###############################################################
#  Generated by:      Cadence Innovus 21.35-s114_1
#  OS:                Linux x86_64(Host ID item0110.item.uni-bremen.de)
#  Generated on:      Fri Aug  9 22:37:40 2024
#  Design:            ibex_core
#  Command:           write_lef_abstract ./results/dummy_ni.lef -stripePin -noCutObs -PGPinLayers M3 -specifyTopLayer M3
###############################################################

VERSION 5.8 ;

BUSBITCHARS "[]" ;
DIVIDERCHAR "/" ;

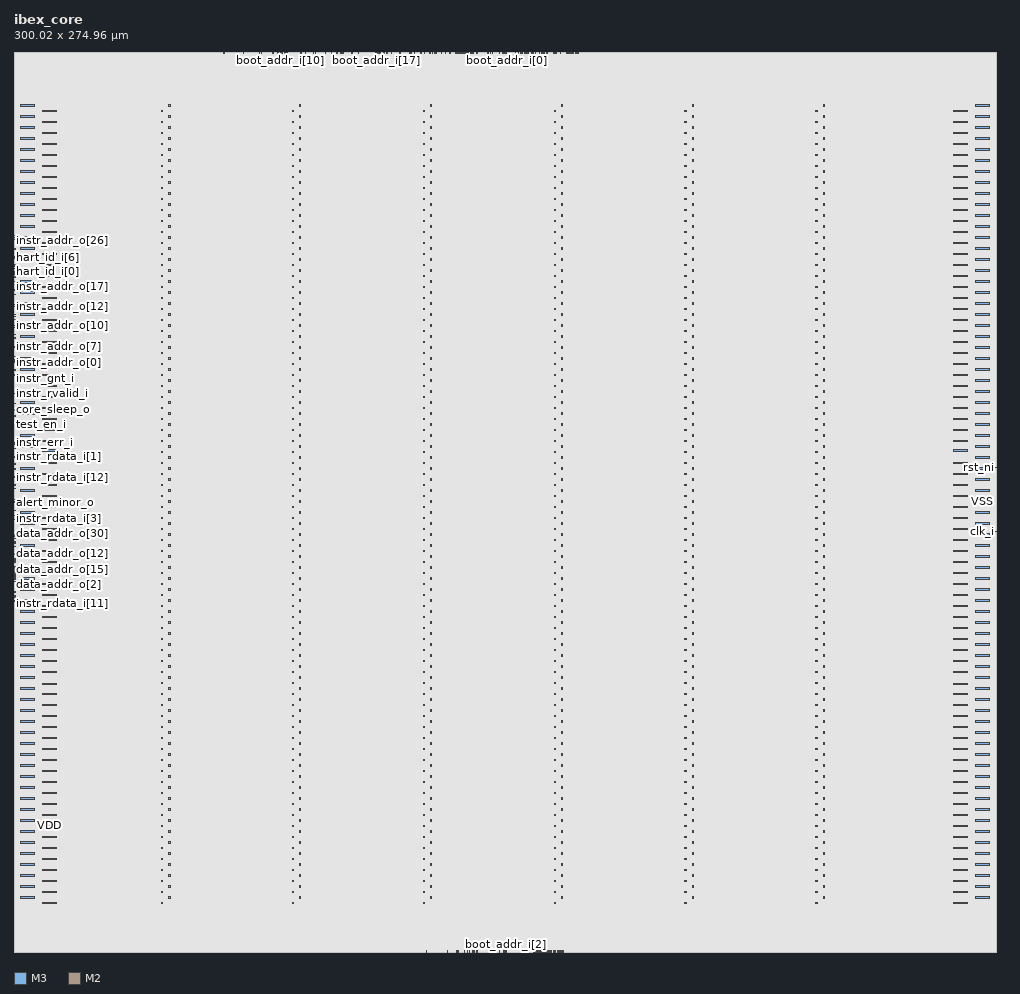
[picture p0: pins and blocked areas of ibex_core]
MACRO ibex_core
  CLASS BLOCK ;
  SIZE 300.020000 BY 274.960000 ;
  FOREIGN ibex_core 0.000000 0.000000 ;
  ORIGIN 0 0 ;
  SYMMETRY X Y R90 ;
  PIN clk_i
    DIRECTION INPUT ;
    USE SIGNAL ;
    PORT
      LAYER M3 ;
        RECT 299.630000 128.485000 300.020000 128.555000 ;
    END
  END clk_i
  PIN rst_ni
    DIRECTION INPUT ;
    USE SIGNAL ;
    PORT
      LAYER M3 ;
        RECT 299.630000 147.945000 300.020000 148.015000 ;
    END
  END rst_ni
  PIN test_en_i
    DIRECTION INPUT ;
    USE SIGNAL ;
    PORT
      LAYER M3 ;
        RECT 0.000000 163.485000 0.390000 163.555000 ;
    END
  END test_en_i
  PIN hart_id_i[31]
    DIRECTION INPUT ;
    USE SIGNAL ;
    PORT
      LAYER M2 ;
        RECT 99.855000 274.570000 99.925000 274.960000 ;
    END
  END hart_id_i[31]
  PIN hart_id_i[30]
    DIRECTION INPUT ;
    USE SIGNAL ;
    PORT
      LAYER M2 ;
        RECT 103.215000 274.570000 103.285000 274.960000 ;
    END
  END hart_id_i[30]
  PIN hart_id_i[29]
    DIRECTION INPUT ;
    USE SIGNAL ;
    PORT
      LAYER M2 ;
        RECT 127.715000 274.570000 127.785000 274.960000 ;
    END
  END hart_id_i[29]
  PIN hart_id_i[28]
    DIRECTION INPUT ;
    USE SIGNAL ;
    PORT
      LAYER M2 ;
        RECT 136.955000 274.570000 137.025000 274.960000 ;
    END
  END hart_id_i[28]
  PIN hart_id_i[27]
    DIRECTION INPUT ;
    USE SIGNAL ;
    PORT
      LAYER M2 ;
        RECT 137.795000 274.570000 137.865000 274.960000 ;
    END
  END hart_id_i[27]
  PIN hart_id_i[26]
    DIRECTION INPUT ;
    USE SIGNAL ;
    PORT
      LAYER M2 ;
        RECT 135.835000 274.570000 135.905000 274.960000 ;
    END
  END hart_id_i[26]
  PIN hart_id_i[25]
    DIRECTION INPUT ;
    USE SIGNAL ;
    PORT
      LAYER M2 ;
        RECT 137.515000 274.570000 137.585000 274.960000 ;
    END
  END hart_id_i[25]
  PIN hart_id_i[24]
    DIRECTION INPUT ;
    USE SIGNAL ;
    PORT
      LAYER M2 ;
        RECT 138.355000 274.570000 138.425000 274.960000 ;
    END
  END hart_id_i[24]
  PIN hart_id_i[23]
    DIRECTION INPUT ;
    USE SIGNAL ;
    PORT
      LAYER M2 ;
        RECT 139.335000 274.570000 139.405000 274.960000 ;
    END
  END hart_id_i[23]
  PIN hart_id_i[22]
    DIRECTION INPUT ;
    USE SIGNAL ;
    PORT
      LAYER M2 ;
        RECT 138.915000 274.570000 138.985000 274.960000 ;
    END
  END hart_id_i[22]
  PIN hart_id_i[21]
    DIRECTION INPUT ;
    USE SIGNAL ;
    PORT
      LAYER M2 ;
        RECT 110.355000 274.570000 110.425000 274.960000 ;
    END
  END hart_id_i[21]
  PIN hart_id_i[20]
    DIRECTION INPUT ;
    USE SIGNAL ;
    PORT
      LAYER M2 ;
        RECT 121.275000 274.570000 121.345000 274.960000 ;
    END
  END hart_id_i[20]
  PIN hart_id_i[19]
    DIRECTION INPUT ;
    USE SIGNAL ;
    PORT
      LAYER M2 ;
        RECT 113.715000 274.570000 113.785000 274.960000 ;
    END
  END hart_id_i[19]
  PIN hart_id_i[18]
    DIRECTION INPUT ;
    USE SIGNAL ;
    PORT
      LAYER M2 ;
        RECT 124.075000 274.570000 124.145000 274.960000 ;
    END
  END hart_id_i[18]
  PIN hart_id_i[17]
    DIRECTION INPUT ;
    USE SIGNAL ;
    PORT
      LAYER M2 ;
        RECT 111.055000 274.570000 111.125000 274.960000 ;
    END
  END hart_id_i[17]
  PIN hart_id_i[16]
    DIRECTION INPUT ;
    USE SIGNAL ;
    PORT
      LAYER M2 ;
        RECT 128.555000 274.570000 128.625000 274.960000 ;
    END
  END hart_id_i[16]
  PIN hart_id_i[15]
    DIRECTION INPUT ;
    USE SIGNAL ;
    PORT
      LAYER M2 ;
        RECT 100.695000 274.570000 100.765000 274.960000 ;
    END
  END hart_id_i[15]
  PIN hart_id_i[14]
    DIRECTION INPUT ;
    USE SIGNAL ;
    PORT
      LAYER M2 ;
        RECT 100.415000 274.570000 100.485000 274.960000 ;
    END
  END hart_id_i[14]
  PIN hart_id_i[13]
    DIRECTION INPUT ;
    USE SIGNAL ;
    PORT
      LAYER M2 ;
        RECT 91.455000 274.570000 91.525000 274.960000 ;
    END
  END hart_id_i[13]
  PIN hart_id_i[12]
    DIRECTION INPUT ;
    USE SIGNAL ;
    PORT
      LAYER M2 ;
        RECT 89.075000 274.570000 89.145000 274.960000 ;
    END
  END hart_id_i[12]
  PIN hart_id_i[11]
    DIRECTION INPUT ;
    USE SIGNAL ;
    PORT
      LAYER M2 ;
        RECT 80.815000 274.570000 80.885000 274.960000 ;
    END
  END hart_id_i[11]
  PIN hart_id_i[10]
    DIRECTION INPUT ;
    USE SIGNAL ;
    PORT
      LAYER M2 ;
        RECT 80.535000 274.570000 80.605000 274.960000 ;
    END
  END hart_id_i[10]
  PIN hart_id_i[9]
    DIRECTION INPUT ;
    USE SIGNAL ;
    PORT
      LAYER M2 ;
        RECT 83.335000 274.570000 83.405000 274.960000 ;
    END
  END hart_id_i[9]
  PIN hart_id_i[8]
    DIRECTION INPUT ;
    USE SIGNAL ;
    PORT
      LAYER M2 ;
        RECT 79.275000 274.570000 79.345000 274.960000 ;
    END
  END hart_id_i[8]
  PIN hart_id_i[7]
    DIRECTION INPUT ;
    USE SIGNAL ;
    PORT
      LAYER M3 ;
        RECT 0.000000 207.305000 0.390000 207.375000 ;
    END
  END hart_id_i[7]
  PIN hart_id_i[6]
    DIRECTION INPUT ;
    USE SIGNAL ;
    PORT
      LAYER M3 ;
        RECT 0.000000 212.205000 0.390000 212.275000 ;
    END
  END hart_id_i[6]
  PIN hart_id_i[5]
    DIRECTION INPUT ;
    USE SIGNAL ;
    PORT
      LAYER M2 ;
        RECT 64.155000 274.570000 64.225000 274.960000 ;
    END
  END hart_id_i[5]
  PIN hart_id_i[4]
    DIRECTION INPUT ;
    USE SIGNAL ;
    PORT
      LAYER M3 ;
        RECT 0.000000 207.585000 0.390000 207.655000 ;
    END
  END hart_id_i[4]
  PIN hart_id_i[3]
    DIRECTION INPUT ;
    USE SIGNAL ;
    PORT
      LAYER M2 ;
        RECT 75.495000 274.570000 75.565000 274.960000 ;
    END
  END hart_id_i[3]
  PIN hart_id_i[2]
    DIRECTION INPUT ;
    USE SIGNAL ;
    PORT
      LAYER M2 ;
        RECT 70.175000 274.570000 70.245000 274.960000 ;
    END
  END hart_id_i[2]
  PIN hart_id_i[1]
    DIRECTION INPUT ;
    USE SIGNAL ;
    PORT
      LAYER M3 ;
        RECT 0.000000 208.845000 0.390000 208.915000 ;
    END
  END hart_id_i[1]
  PIN hart_id_i[0]
    DIRECTION INPUT ;
    USE SIGNAL ;
    PORT
      LAYER M3 ;
        RECT 0.000000 207.865000 0.390000 207.935000 ;
    END
  END hart_id_i[0]
  PIN boot_addr_i[31]
    DIRECTION INPUT ;
    USE SIGNAL ;
    PORT
      LAYER M2 ;
        RECT 95.235000 274.570000 95.305000 274.960000 ;
    END
  END boot_addr_i[31]
  PIN boot_addr_i[30]
    DIRECTION INPUT ;
    USE SIGNAL ;
    PORT
      LAYER M2 ;
        RECT 105.315000 274.570000 105.385000 274.960000 ;
    END
  END boot_addr_i[30]
  PIN boot_addr_i[29]
    DIRECTION INPUT ;
    USE SIGNAL ;
    PORT
      LAYER M2 ;
        RECT 113.015000 274.570000 113.085000 274.960000 ;
    END
  END boot_addr_i[29]
  PIN boot_addr_i[28]
    DIRECTION INPUT ;
    USE SIGNAL ;
    PORT
      LAYER M2 ;
        RECT 128.975000 274.570000 129.045000 274.960000 ;
    END
  END boot_addr_i[28]
  PIN boot_addr_i[27]
    DIRECTION INPUT ;
    USE SIGNAL ;
    PORT
      LAYER M2 ;
        RECT 133.175000 274.570000 133.245000 274.960000 ;
    END
  END boot_addr_i[27]
  PIN boot_addr_i[26]
    DIRECTION INPUT ;
    USE SIGNAL ;
    PORT
      LAYER M2 ;
        RECT 135.135000 274.570000 135.205000 274.960000 ;
    END
  END boot_addr_i[26]
  PIN boot_addr_i[25]
    DIRECTION INPUT ;
    USE SIGNAL ;
    PORT
      LAYER M2 ;
        RECT 134.855000 274.570000 134.925000 274.960000 ;
    END
  END boot_addr_i[25]
  PIN boot_addr_i[24]
    DIRECTION INPUT ;
    USE SIGNAL ;
    PORT
      LAYER M2 ;
        RECT 136.395000 274.570000 136.465000 274.960000 ;
    END
  END boot_addr_i[24]
  PIN boot_addr_i[23]
    DIRECTION INPUT ;
    USE SIGNAL ;
    PORT
      LAYER M2 ;
        RECT 136.675000 274.570000 136.745000 274.960000 ;
    END
  END boot_addr_i[23]
  PIN boot_addr_i[22]
    DIRECTION INPUT ;
    USE SIGNAL ;
    PORT
      LAYER M2 ;
        RECT 131.775000 274.570000 131.845000 274.960000 ;
    END
  END boot_addr_i[22]
  PIN boot_addr_i[21]
    DIRECTION INPUT ;
    USE SIGNAL ;
    PORT
      LAYER M2 ;
        RECT 112.035000 274.570000 112.105000 274.960000 ;
    END
  END boot_addr_i[21]
  PIN boot_addr_i[20]
    DIRECTION INPUT ;
    USE SIGNAL ;
    PORT
      LAYER M2 ;
        RECT 115.395000 274.570000 115.465000 274.960000 ;
    END
  END boot_addr_i[20]
  PIN boot_addr_i[19]
    DIRECTION INPUT ;
    USE SIGNAL ;
    PORT
      LAYER M2 ;
        RECT 122.255000 274.570000 122.325000 274.960000 ;
    END
  END boot_addr_i[19]
  PIN boot_addr_i[18]
    DIRECTION INPUT ;
    USE SIGNAL ;
    PORT
      LAYER M2 ;
        RECT 125.475000 274.570000 125.545000 274.960000 ;
    END
  END boot_addr_i[18]
  PIN boot_addr_i[17]
    DIRECTION INPUT ;
    USE SIGNAL ;
    PORT
      LAYER M2 ;
        RECT 110.775000 274.570000 110.845000 274.960000 ;
    END
  END boot_addr_i[17]
  PIN boot_addr_i[16]
    DIRECTION INPUT ;
    USE SIGNAL ;
    PORT
      LAYER M2 ;
        RECT 127.295000 274.570000 127.365000 274.960000 ;
    END
  END boot_addr_i[16]
  PIN boot_addr_i[15]
    DIRECTION INPUT ;
    USE SIGNAL ;
    PORT
      LAYER M2 ;
        RECT 98.595000 274.570000 98.665000 274.960000 ;
    END
  END boot_addr_i[15]
  PIN boot_addr_i[14]
    DIRECTION INPUT ;
    USE SIGNAL ;
    PORT
      LAYER M2 ;
        RECT 96.915000 274.570000 96.985000 274.960000 ;
    END
  END boot_addr_i[14]
  PIN boot_addr_i[13]
    DIRECTION INPUT ;
    USE SIGNAL ;
    PORT
      LAYER M2 ;
        RECT 92.015000 274.570000 92.085000 274.960000 ;
    END
  END boot_addr_i[13]
  PIN boot_addr_i[12]
    DIRECTION INPUT ;
    USE SIGNAL ;
    PORT
      LAYER M2 ;
        RECT 87.675000 274.570000 87.745000 274.960000 ;
    END
  END boot_addr_i[12]
  PIN boot_addr_i[11]
    DIRECTION INPUT ;
    USE SIGNAL ;
    PORT
      LAYER M2 ;
        RECT 82.775000 274.570000 82.845000 274.960000 ;
    END
  END boot_addr_i[11]
  PIN boot_addr_i[10]
    DIRECTION INPUT ;
    USE SIGNAL ;
    PORT
      LAYER M2 ;
        RECT 81.515000 274.570000 81.585000 274.960000 ;
    END
  END boot_addr_i[10]
  PIN boot_addr_i[9]
    DIRECTION INPUT ;
    USE SIGNAL ;
    PORT
      LAYER M2 ;
        RECT 83.615000 274.570000 83.685000 274.960000 ;
    END
  END boot_addr_i[9]
  PIN boot_addr_i[8]
    DIRECTION INPUT ;
    USE SIGNAL ;
    PORT
      LAYER M2 ;
        RECT 82.075000 274.570000 82.145000 274.960000 ;
    END
  END boot_addr_i[8]
  PIN boot_addr_i[7]
    DIRECTION INPUT ;
    USE SIGNAL ;
    PORT
      LAYER M2 ;
        RECT 149.975000 274.570000 150.045000 274.960000 ;
    END
  END boot_addr_i[7]
  PIN boot_addr_i[6]
    DIRECTION INPUT ;
    USE SIGNAL ;
    PORT
      LAYER M2 ;
        RECT 149.975000 0.000000 150.045000 0.390000 ;
    END
  END boot_addr_i[6]
  PIN boot_addr_i[5]
    DIRECTION INPUT ;
    USE SIGNAL ;
    PORT
      LAYER M2 ;
        RECT 149.695000 274.570000 149.765000 274.960000 ;
    END
  END boot_addr_i[5]
  PIN boot_addr_i[4]
    DIRECTION INPUT ;
    USE SIGNAL ;
    PORT
      LAYER M2 ;
        RECT 150.255000 274.570000 150.325000 274.960000 ;
    END
  END boot_addr_i[4]
  PIN boot_addr_i[3]
    DIRECTION INPUT ;
    USE SIGNAL ;
    PORT
      LAYER M2 ;
        RECT 149.695000 0.000000 149.765000 0.390000 ;
    END
  END boot_addr_i[3]
  PIN boot_addr_i[2]
    DIRECTION INPUT ;
    USE SIGNAL ;
    PORT
      LAYER M2 ;
        RECT 150.255000 0.000000 150.325000 0.390000 ;
    END
  END boot_addr_i[2]
  PIN boot_addr_i[1]
    DIRECTION INPUT ;
    USE SIGNAL ;
    PORT
      LAYER M2 ;
        RECT 149.415000 274.570000 149.485000 274.960000 ;
    END
  END boot_addr_i[1]
  PIN boot_addr_i[0]
    DIRECTION INPUT ;
    USE SIGNAL ;
    PORT
      LAYER M2 ;
        RECT 150.535000 274.570000 150.605000 274.960000 ;
    END
  END boot_addr_i[0]
  PIN instr_req_o
    DIRECTION OUTPUT ;
    USE SIGNAL ;
    PORT
      LAYER M3 ;
        RECT 0.000000 176.225000 0.390000 176.295000 ;
    END
  END instr_req_o
  PIN instr_gnt_i
    DIRECTION INPUT ;
    USE SIGNAL ;
    PORT
      LAYER M3 ;
        RECT 0.000000 177.625000 0.390000 177.695000 ;
    END
  END instr_gnt_i
  PIN instr_rvalid_i
    DIRECTION INPUT ;
    USE SIGNAL ;
    PORT
      LAYER M3 ;
        RECT 0.000000 170.485000 0.390000 170.555000 ;
    END
  END instr_rvalid_i
  PIN instr_addr_o[31]
    DIRECTION OUTPUT ;
    USE SIGNAL ;
    PORT
      LAYER M3 ;
        RECT 0.000000 214.725000 0.390000 214.795000 ;
    END
  END instr_addr_o[31]
  PIN instr_addr_o[30]
    DIRECTION OUTPUT ;
    USE SIGNAL ;
    PORT
      LAYER M3 ;
        RECT 0.000000 218.365000 0.390000 218.435000 ;
    END
  END instr_addr_o[30]
  PIN instr_addr_o[29]
    DIRECTION OUTPUT ;
    USE SIGNAL ;
    PORT
      LAYER M3 ;
        RECT 0.000000 218.785000 0.390000 218.855000 ;
    END
  END instr_addr_o[29]
  PIN instr_addr_o[28]
    DIRECTION OUTPUT ;
    USE SIGNAL ;
    PORT
      LAYER M3 ;
        RECT 0.000000 217.525000 0.390000 217.595000 ;
    END
  END instr_addr_o[28]
  PIN instr_addr_o[27]
    DIRECTION OUTPUT ;
    USE SIGNAL ;
    PORT
      LAYER M3 ;
        RECT 0.000000 211.925000 0.390000 211.995000 ;
    END
  END instr_addr_o[27]
  PIN instr_addr_o[26]
    DIRECTION OUTPUT ;
    USE SIGNAL ;
    PORT
      LAYER M3 ;
        RECT 0.000000 215.005000 0.390000 215.075000 ;
    END
  END instr_addr_o[26]
  PIN instr_addr_o[25]
    DIRECTION OUTPUT ;
    USE SIGNAL ;
    PORT
      LAYER M3 ;
        RECT 0.000000 209.545000 0.390000 209.615000 ;
    END
  END instr_addr_o[25]
  PIN instr_addr_o[24]
    DIRECTION OUTPUT ;
    USE SIGNAL ;
    PORT
      LAYER M3 ;
        RECT 0.000000 212.485000 0.390000 212.555000 ;
    END
  END instr_addr_o[24]
  PIN instr_addr_o[23]
    DIRECTION OUTPUT ;
    USE SIGNAL ;
    PORT
      LAYER M3 ;
        RECT 0.000000 207.025000 0.390000 207.095000 ;
    END
  END instr_addr_o[23]
  PIN instr_addr_o[22]
    DIRECTION OUTPUT ;
    USE SIGNAL ;
    PORT
      LAYER M3 ;
        RECT 0.000000 209.825000 0.390000 209.895000 ;
    END
  END instr_addr_o[22]
  PIN instr_addr_o[21]
    DIRECTION OUTPUT ;
    USE SIGNAL ;
    PORT
      LAYER M3 ;
        RECT 0.000000 206.185000 0.390000 206.255000 ;
    END
  END instr_addr_o[21]
  PIN instr_addr_o[20]
    DIRECTION OUTPUT ;
    USE SIGNAL ;
    PORT
      LAYER M3 ;
        RECT 0.000000 204.925000 0.390000 204.995000 ;
    END
  END instr_addr_o[20]
  PIN instr_addr_o[19]
    DIRECTION OUTPUT ;
    USE SIGNAL ;
    PORT
      LAYER M3 ;
        RECT 0.000000 201.985000 0.390000 202.055000 ;
    END
  END instr_addr_o[19]
  PIN instr_addr_o[18]
    DIRECTION OUTPUT ;
    USE SIGNAL ;
    PORT
      LAYER M3 ;
        RECT 0.000000 202.265000 0.390000 202.335000 ;
    END
  END instr_addr_o[18]
  PIN instr_addr_o[17]
    DIRECTION OUTPUT ;
    USE SIGNAL ;
    PORT
      LAYER M3 ;
        RECT 0.000000 200.725000 0.390000 200.795000 ;
    END
  END instr_addr_o[17]
  PIN instr_addr_o[16]
    DIRECTION OUTPUT ;
    USE SIGNAL ;
    PORT
      LAYER M3 ;
        RECT 0.000000 197.785000 0.390000 197.855000 ;
    END
  END instr_addr_o[16]
  PIN instr_addr_o[15]
    DIRECTION OUTPUT ;
    USE SIGNAL ;
    PORT
      LAYER M3 ;
        RECT 0.000000 197.085000 0.390000 197.155000 ;
    END
  END instr_addr_o[15]
  PIN instr_addr_o[14]
    DIRECTION OUTPUT ;
    USE SIGNAL ;
    PORT
      LAYER M3 ;
        RECT 0.000000 194.005000 0.390000 194.075000 ;
    END
  END instr_addr_o[14]
  PIN instr_addr_o[13]
    DIRECTION OUTPUT ;
    USE SIGNAL ;
    PORT
      LAYER M3 ;
        RECT 0.000000 193.165000 0.390000 193.235000 ;
    END
  END instr_addr_o[13]
  PIN instr_addr_o[12]
    DIRECTION OUTPUT ;
    USE SIGNAL ;
    PORT
      LAYER M3 ;
        RECT 0.000000 194.845000 0.390000 194.915000 ;
    END
  END instr_addr_o[12]
  PIN instr_addr_o[11]
    DIRECTION OUTPUT ;
    USE SIGNAL ;
    PORT
      LAYER M3 ;
        RECT 0.000000 188.545000 0.390000 188.615000 ;
    END
  END instr_addr_o[11]
  PIN instr_addr_o[10]
    DIRECTION OUTPUT ;
    USE SIGNAL ;
    PORT
      LAYER M3 ;
        RECT 0.000000 191.485000 0.390000 191.555000 ;
    END
  END instr_addr_o[10]
  PIN instr_addr_o[9]
    DIRECTION OUTPUT ;
    USE SIGNAL ;
    PORT
      LAYER M3 ;
        RECT 0.000000 187.705000 0.390000 187.775000 ;
    END
  END instr_addr_o[9]
  PIN instr_addr_o[8]
    DIRECTION OUTPUT ;
    USE SIGNAL ;
    PORT
      LAYER M3 ;
        RECT 0.000000 190.645000 0.390000 190.715000 ;
    END
  END instr_addr_o[8]
  PIN instr_addr_o[7]
    DIRECTION OUTPUT ;
    USE SIGNAL ;
    PORT
      LAYER M3 ;
        RECT 0.000000 187.285000 0.390000 187.355000 ;
    END
  END instr_addr_o[7]
  PIN instr_addr_o[6]
    DIRECTION OUTPUT ;
    USE SIGNAL ;
    PORT
      LAYER M3 ;
        RECT 0.000000 184.765000 0.390000 184.835000 ;
    END
  END instr_addr_o[6]
  PIN instr_addr_o[5]
    DIRECTION OUTPUT ;
    USE SIGNAL ;
    PORT
      LAYER M3 ;
        RECT 0.000000 181.825000 0.390000 181.895000 ;
    END
  END instr_addr_o[5]
  PIN instr_addr_o[4]
    DIRECTION OUTPUT ;
    USE SIGNAL ;
    PORT
      LAYER M3 ;
        RECT 0.000000 185.045000 0.390000 185.115000 ;
    END
  END instr_addr_o[4]
  PIN instr_addr_o[3]
    DIRECTION OUTPUT ;
    USE SIGNAL ;
    PORT
      LAYER M3 ;
        RECT 0.000000 180.985000 0.390000 181.055000 ;
    END
  END instr_addr_o[3]
  PIN instr_addr_o[2]
    DIRECTION OUTPUT ;
    USE SIGNAL ;
    PORT
      LAYER M3 ;
        RECT 0.000000 180.565000 0.390000 180.635000 ;
    END
  END instr_addr_o[2]
  PIN instr_addr_o[1]
    DIRECTION OUTPUT ;
    USE SIGNAL ;
    PORT
      LAYER M3 ;
        RECT 0.000000 180.285000 0.390000 180.355000 ;
    END
  END instr_addr_o[1]
  PIN instr_addr_o[0]
    DIRECTION OUTPUT ;
    USE SIGNAL ;
    PORT
      LAYER M3 ;
        RECT 0.000000 180.005000 0.390000 180.075000 ;
    END
  END instr_addr_o[0]
  PIN instr_rdata_i[31]
    DIRECTION INPUT ;
    USE SIGNAL ;
    PORT
      LAYER M3 ;
        RECT 0.000000 124.985000 0.390000 125.055000 ;
    END
  END instr_rdata_i[31]
  PIN instr_rdata_i[30]
    DIRECTION INPUT ;
    USE SIGNAL ;
    PORT
      LAYER M3 ;
        RECT 0.000000 126.385000 0.390000 126.455000 ;
    END
  END instr_rdata_i[30]
  PIN instr_rdata_i[29]
    DIRECTION INPUT ;
    USE SIGNAL ;
    PORT
      LAYER M3 ;
        RECT 0.000000 119.385000 0.390000 119.455000 ;
    END
  END instr_rdata_i[29]
  PIN instr_rdata_i[28]
    DIRECTION INPUT ;
    USE SIGNAL ;
    PORT
      LAYER M3 ;
        RECT 0.000000 149.065000 0.390000 149.135000 ;
    END
  END instr_rdata_i[28]
  PIN instr_rdata_i[27]
    DIRECTION INPUT ;
    USE SIGNAL ;
    PORT
      LAYER M3 ;
        RECT 0.000000 110.145000 0.390000 110.215000 ;
    END
  END instr_rdata_i[27]
  PIN instr_rdata_i[26]
    DIRECTION INPUT ;
    USE SIGNAL ;
    PORT
      LAYER M3 ;
        RECT 0.000000 127.365000 0.390000 127.435000 ;
    END
  END instr_rdata_i[26]
  PIN instr_rdata_i[25]
    DIRECTION INPUT ;
    USE SIGNAL ;
    PORT
      LAYER M3 ;
        RECT 0.000000 133.385000 0.390000 133.455000 ;
    END
  END instr_rdata_i[25]
  PIN instr_rdata_i[24]
    DIRECTION INPUT ;
    USE SIGNAL ;
    PORT
      LAYER M3 ;
        RECT 0.000000 147.525000 0.390000 147.595000 ;
    END
  END instr_rdata_i[24]
  PIN instr_rdata_i[23]
    DIRECTION INPUT ;
    USE SIGNAL ;
    PORT
      LAYER M3 ;
        RECT 0.000000 142.765000 0.390000 142.835000 ;
    END
  END instr_rdata_i[23]
  PIN instr_rdata_i[22]
    DIRECTION INPUT ;
    USE SIGNAL ;
    PORT
      LAYER M3 ;
        RECT 0.000000 115.745000 0.390000 115.815000 ;
    END
  END instr_rdata_i[22]
  PIN instr_rdata_i[21]
    DIRECTION INPUT ;
    USE SIGNAL ;
    PORT
      LAYER M3 ;
        RECT 0.000000 108.605000 0.390000 108.675000 ;
    END
  END instr_rdata_i[21]
  PIN instr_rdata_i[20]
    DIRECTION INPUT ;
    USE SIGNAL ;
    PORT
      LAYER M3 ;
        RECT 0.000000 145.145000 0.390000 145.215000 ;
    END
  END instr_rdata_i[20]
  PIN instr_rdata_i[19]
    DIRECTION INPUT ;
    USE SIGNAL ;
    PORT
      LAYER M3 ;
        RECT 0.000000 138.145000 0.390000 138.215000 ;
    END
  END instr_rdata_i[19]
  PIN instr_rdata_i[18]
    DIRECTION INPUT ;
    USE SIGNAL ;
    PORT
      LAYER M3 ;
        RECT 0.000000 131.985000 0.390000 132.055000 ;
    END
  END instr_rdata_i[18]
  PIN instr_rdata_i[17]
    DIRECTION INPUT ;
    USE SIGNAL ;
    PORT
      LAYER M3 ;
        RECT 0.000000 153.685000 0.390000 153.755000 ;
    END
  END instr_rdata_i[17]
  PIN instr_rdata_i[16]
    DIRECTION INPUT ;
    USE SIGNAL ;
    PORT
      LAYER M3 ;
        RECT 0.000000 155.085000 0.390000 155.155000 ;
    END
  END instr_rdata_i[16]
  PIN instr_rdata_i[15]
    DIRECTION INPUT ;
    USE SIGNAL ;
    PORT
      LAYER M3 ;
        RECT 0.000000 119.665000 0.390000 119.735000 ;
    END
  END instr_rdata_i[15]
  PIN instr_rdata_i[14]
    DIRECTION INPUT ;
    USE SIGNAL ;
    PORT
      LAYER M3 ;
        RECT 0.000000 109.865000 0.390000 109.935000 ;
    END
  END instr_rdata_i[14]
  PIN instr_rdata_i[13]
    DIRECTION INPUT ;
    USE SIGNAL ;
    PORT
      LAYER M3 ;
        RECT 0.000000 108.325000 0.390000 108.395000 ;
    END
  END instr_rdata_i[13]
  PIN instr_rdata_i[12]
    DIRECTION INPUT ;
    USE SIGNAL ;
    PORT
      LAYER M3 ;
        RECT 0.000000 144.865000 0.390000 144.935000 ;
    END
  END instr_rdata_i[12]
  PIN instr_rdata_i[11]
    DIRECTION INPUT ;
    USE SIGNAL ;
    PORT
      LAYER M3 ;
        RECT 0.000000 108.885000 0.390000 108.955000 ;
    END
  END instr_rdata_i[11]
  PIN instr_rdata_i[10]
    DIRECTION INPUT ;
    USE SIGNAL ;
    PORT
      LAYER M3 ;
        RECT 0.000000 117.705000 0.390000 117.775000 ;
    END
  END instr_rdata_i[10]
  PIN instr_rdata_i[9]
    DIRECTION INPUT ;
    USE SIGNAL ;
    PORT
      LAYER M3 ;
        RECT 0.000000 124.705000 0.390000 124.775000 ;
    END
  END instr_rdata_i[9]
  PIN instr_rdata_i[8]
    DIRECTION INPUT ;
    USE SIGNAL ;
    PORT
      LAYER M3 ;
        RECT 0.000000 141.645000 0.390000 141.715000 ;
    END
  END instr_rdata_i[8]
  PIN instr_rdata_i[7]
    DIRECTION INPUT ;
    USE SIGNAL ;
    PORT
      LAYER M3 ;
        RECT 0.000000 137.585000 0.390000 137.655000 ;
    END
  END instr_rdata_i[7]
  PIN instr_rdata_i[6]
    DIRECTION INPUT ;
    USE SIGNAL ;
    PORT
      LAYER M3 ;
        RECT 0.000000 113.225000 0.390000 113.295000 ;
    END
  END instr_rdata_i[6]
  PIN instr_rdata_i[5]
    DIRECTION INPUT ;
    USE SIGNAL ;
    PORT
      LAYER M3 ;
        RECT 0.000000 107.205000 0.390000 107.275000 ;
    END
  END instr_rdata_i[5]
  PIN instr_rdata_i[4]
    DIRECTION INPUT ;
    USE SIGNAL ;
    PORT
      LAYER M3 ;
        RECT 0.000000 142.485000 0.390000 142.555000 ;
    END
  END instr_rdata_i[4]
  PIN instr_rdata_i[3]
    DIRECTION INPUT ;
    USE SIGNAL ;
    PORT
      LAYER M3 ;
        RECT 0.000000 134.925000 0.390000 134.995000 ;
    END
  END instr_rdata_i[3]
  PIN instr_rdata_i[2]
    DIRECTION INPUT ;
    USE SIGNAL ;
    PORT
      LAYER M3 ;
        RECT 0.000000 127.085000 0.390000 127.155000 ;
    END
  END instr_rdata_i[2]
  PIN instr_rdata_i[1]
    DIRECTION INPUT ;
    USE SIGNAL ;
    PORT
      LAYER M3 ;
        RECT 0.000000 148.785000 0.390000 148.855000 ;
    END
  END instr_rdata_i[1]
  PIN instr_rdata_i[0]
    DIRECTION INPUT ;
    USE SIGNAL ;
    PORT
      LAYER M3 ;
        RECT 0.000000 151.165000 0.390000 151.235000 ;
    END
  END instr_rdata_i[0]
  PIN instr_err_i
    DIRECTION INPUT ;
    USE SIGNAL ;
    PORT
      LAYER M3 ;
        RECT 0.000000 155.505000 0.390000 155.575000 ;
    END
  END instr_err_i
  PIN data_req_o
    DIRECTION OUTPUT ;
    USE SIGNAL ;
    PORT
      LAYER M2 ;
        RECT 145.495000 274.570000 145.565000 274.960000 ;
    END
  END data_req_o
  PIN data_gnt_i
    DIRECTION INPUT ;
    USE SIGNAL ;
    PORT
      LAYER M2 ;
        RECT 148.295000 274.570000 148.365000 274.960000 ;
    END
  END data_gnt_i
  PIN data_rvalid_i
    DIRECTION INPUT ;
    USE SIGNAL ;
    PORT
      LAYER M2 ;
        RECT 144.795000 274.570000 144.865000 274.960000 ;
    END
  END data_rvalid_i
  PIN data_we_o
    DIRECTION OUTPUT ;
    USE SIGNAL ;
    PORT
      LAYER M2 ;
        RECT 113.995000 274.570000 114.065000 274.960000 ;
    END
  END data_we_o
  PIN data_be_o[3]
    DIRECTION OUTPUT ;
    USE SIGNAL ;
    PORT
      LAYER M2 ;
        RECT 156.275000 274.570000 156.345000 274.960000 ;
    END
  END data_be_o[3]
  PIN data_be_o[2]
    DIRECTION OUTPUT ;
    USE SIGNAL ;
    PORT
      LAYER M2 ;
        RECT 160.475000 274.570000 160.545000 274.960000 ;
    END
  END data_be_o[2]
  PIN data_be_o[1]
    DIRECTION OUTPUT ;
    USE SIGNAL ;
    PORT
      LAYER M2 ;
        RECT 159.215000 274.570000 159.285000 274.960000 ;
    END
  END data_be_o[1]
  PIN data_be_o[0]
    DIRECTION OUTPUT ;
    USE SIGNAL ;
    PORT
      LAYER M2 ;
        RECT 161.175000 274.570000 161.245000 274.960000 ;
    END
  END data_be_o[0]
  PIN data_addr_o[31]
    DIRECTION OUTPUT ;
    USE SIGNAL ;
    PORT
      LAYER M3 ;
        RECT 0.000000 123.865000 0.390000 123.935000 ;
    END
  END data_addr_o[31]
  PIN data_addr_o[30]
    DIRECTION OUTPUT ;
    USE SIGNAL ;
    PORT
      LAYER M3 ;
        RECT 0.000000 125.405000 0.390000 125.475000 ;
    END
  END data_addr_o[30]
  PIN data_addr_o[29]
    DIRECTION OUTPUT ;
    USE SIGNAL ;
    PORT
      LAYER M2 ;
        RECT 126.035000 0.000000 126.105000 0.390000 ;
    END
  END data_addr_o[29]
  PIN data_addr_o[28]
    DIRECTION OUTPUT ;
    USE SIGNAL ;
    PORT
      LAYER M2 ;
        RECT 132.475000 0.000000 132.545000 0.390000 ;
    END
  END data_addr_o[28]
  PIN data_addr_o[27]
    DIRECTION OUTPUT ;
    USE SIGNAL ;
    PORT
      LAYER M2 ;
        RECT 135.835000 0.000000 135.905000 0.390000 ;
    END
  END data_addr_o[27]
  PIN data_addr_o[26]
    DIRECTION OUTPUT ;
    USE SIGNAL ;
    PORT
      LAYER M2 ;
        RECT 139.055000 0.000000 139.125000 0.390000 ;
    END
  END data_addr_o[26]
  PIN data_addr_o[25]
    DIRECTION OUTPUT ;
    USE SIGNAL ;
    PORT
      LAYER M2 ;
        RECT 141.435000 0.000000 141.505000 0.390000 ;
    END
  END data_addr_o[25]
  PIN data_addr_o[24]
    DIRECTION OUTPUT ;
    USE SIGNAL ;
    PORT
      LAYER M2 ;
        RECT 145.635000 0.000000 145.705000 0.390000 ;
    END
  END data_addr_o[24]
  PIN data_addr_o[23]
    DIRECTION OUTPUT ;
    USE SIGNAL ;
    PORT
      LAYER M2 ;
        RECT 145.915000 0.000000 145.985000 0.390000 ;
    END
  END data_addr_o[23]
  PIN data_addr_o[22]
    DIRECTION OUTPUT ;
    USE SIGNAL ;
    PORT
      LAYER M2 ;
        RECT 148.295000 0.000000 148.365000 0.390000 ;
    END
  END data_addr_o[22]
  PIN data_addr_o[21]
    DIRECTION OUTPUT ;
    USE SIGNAL ;
    PORT
      LAYER M2 ;
        RECT 140.455000 0.000000 140.525000 0.390000 ;
    END
  END data_addr_o[21]
  PIN data_addr_o[20]
    DIRECTION OUTPUT ;
    USE SIGNAL ;
    PORT
      LAYER M2 ;
        RECT 140.735000 0.000000 140.805000 0.390000 ;
    END
  END data_addr_o[20]
  PIN data_addr_o[19]
    DIRECTION OUTPUT ;
    USE SIGNAL ;
    PORT
      LAYER M2 ;
        RECT 140.175000 0.000000 140.245000 0.390000 ;
    END
  END data_addr_o[19]
  PIN data_addr_o[18]
    DIRECTION OUTPUT ;
    USE SIGNAL ;
    PORT
      LAYER M2 ;
        RECT 138.495000 0.000000 138.565000 0.390000 ;
    END
  END data_addr_o[18]
  PIN data_addr_o[17]
    DIRECTION OUTPUT ;
    USE SIGNAL ;
    PORT
      LAYER M2 ;
        RECT 137.655000 0.000000 137.725000 0.390000 ;
    END
  END data_addr_o[17]
  PIN data_addr_o[16]
    DIRECTION OUTPUT ;
    USE SIGNAL ;
    PORT
      LAYER M2 ;
        RECT 135.275000 0.000000 135.345000 0.390000 ;
    END
  END data_addr_o[16]
  PIN data_addr_o[15]
    DIRECTION OUTPUT ;
    USE SIGNAL ;
    PORT
      LAYER M3 ;
        RECT 0.000000 119.105000 0.390000 119.175000 ;
    END
  END data_addr_o[15]
  PIN data_addr_o[14]
    DIRECTION OUTPUT ;
    USE SIGNAL ;
    PORT
      LAYER M3 ;
        RECT 0.000000 120.225000 0.390000 120.295000 ;
    END
  END data_addr_o[14]
  PIN data_addr_o[13]
    DIRECTION OUTPUT ;
    USE SIGNAL ;
    PORT
      LAYER M3 ;
        RECT 0.000000 121.485000 0.390000 121.555000 ;
    END
  END data_addr_o[13]
  PIN data_addr_o[12]
    DIRECTION OUTPUT ;
    USE SIGNAL ;
    PORT
      LAYER M3 ;
        RECT 0.000000 121.765000 0.390000 121.835000 ;
    END
  END data_addr_o[12]
  PIN data_addr_o[11]
    DIRECTION OUTPUT ;
    USE SIGNAL ;
    PORT
      LAYER M3 ;
        RECT 0.000000 116.445000 0.390000 116.515000 ;
    END
  END data_addr_o[11]
  PIN data_addr_o[10]
    DIRECTION OUTPUT ;
    USE SIGNAL ;
    PORT
      LAYER M3 ;
        RECT 0.000000 117.145000 0.390000 117.215000 ;
    END
  END data_addr_o[10]
  PIN data_addr_o[9]
    DIRECTION OUTPUT ;
    USE SIGNAL ;
    PORT
      LAYER M3 ;
        RECT 0.000000 117.425000 0.390000 117.495000 ;
    END
  END data_addr_o[9]
  PIN data_addr_o[8]
    DIRECTION OUTPUT ;
    USE SIGNAL ;
    PORT
      LAYER M3 ;
        RECT 0.000000 119.945000 0.390000 120.015000 ;
    END
  END data_addr_o[8]
  PIN data_addr_o[7]
    DIRECTION OUTPUT ;
    USE SIGNAL ;
    PORT
      LAYER M3 ;
        RECT 0.000000 116.025000 0.390000 116.095000 ;
    END
  END data_addr_o[7]
  PIN data_addr_o[6]
    DIRECTION OUTPUT ;
    USE SIGNAL ;
    PORT
      LAYER M3 ;
        RECT 0.000000 114.345000 0.390000 114.415000 ;
    END
  END data_addr_o[6]
  PIN data_addr_o[5]
    DIRECTION OUTPUT ;
    USE SIGNAL ;
    PORT
      LAYER M3 ;
        RECT 0.000000 116.725000 0.390000 116.795000 ;
    END
  END data_addr_o[5]
  PIN data_addr_o[4]
    DIRECTION OUTPUT ;
    USE SIGNAL ;
    PORT
      LAYER M3 ;
        RECT 0.000000 115.465000 0.390000 115.535000 ;
    END
  END data_addr_o[4]
  PIN data_addr_o[3]
    DIRECTION OUTPUT ;
    USE SIGNAL ;
    PORT
      LAYER M3 ;
        RECT 0.000000 115.045000 0.390000 115.115000 ;
    END
  END data_addr_o[3]
  PIN data_addr_o[2]
    DIRECTION OUTPUT ;
    USE SIGNAL ;
    PORT
      LAYER M3 ;
        RECT 0.000000 114.765000 0.390000 114.835000 ;
    END
  END data_addr_o[2]
  PIN data_addr_o[1]
    DIRECTION OUTPUT ;
    USE SIGNAL ;
    PORT
      LAYER M3 ;
        RECT 0.000000 114.065000 0.390000 114.135000 ;
    END
  END data_addr_o[1]
  PIN data_addr_o[0]
    DIRECTION OUTPUT ;
    USE SIGNAL ;
    PORT
      LAYER M3 ;
        RECT 0.000000 113.785000 0.390000 113.855000 ;
    END
  END data_addr_o[0]
  PIN data_wdata_o[31]
    DIRECTION OUTPUT ;
    USE SIGNAL ;
    PORT
      LAYER M2 ;
        RECT 161.595000 0.000000 161.665000 0.390000 ;
    END
  END data_wdata_o[31]
  PIN data_wdata_o[30]
    DIRECTION OUTPUT ;
    USE SIGNAL ;
    PORT
      LAYER M2 ;
        RECT 161.875000 0.000000 161.945000 0.390000 ;
    END
  END data_wdata_o[30]
  PIN data_wdata_o[29]
    DIRECTION OUTPUT ;
    USE SIGNAL ;
    PORT
      LAYER M2 ;
        RECT 165.515000 0.000000 165.585000 0.390000 ;
    END
  END data_wdata_o[29]
  PIN data_wdata_o[28]
    DIRECTION OUTPUT ;
    USE SIGNAL ;
    PORT
      LAYER M2 ;
        RECT 167.055000 0.000000 167.125000 0.390000 ;
    END
  END data_wdata_o[28]
  PIN data_wdata_o[27]
    DIRECTION OUTPUT ;
    USE SIGNAL ;
    PORT
      LAYER M2 ;
        RECT 161.315000 0.000000 161.385000 0.390000 ;
    END
  END data_wdata_o[27]
  PIN data_wdata_o[26]
    DIRECTION OUTPUT ;
    USE SIGNAL ;
    PORT
      LAYER M2 ;
        RECT 164.255000 0.000000 164.325000 0.390000 ;
    END
  END data_wdata_o[26]
  PIN data_wdata_o[25]
    DIRECTION OUTPUT ;
    USE SIGNAL ;
    PORT
      LAYER M2 ;
        RECT 162.295000 0.000000 162.365000 0.390000 ;
    END
  END data_wdata_o[25]
  PIN data_wdata_o[24]
    DIRECTION OUTPUT ;
    USE SIGNAL ;
    PORT
      LAYER M2 ;
        RECT 163.975000 0.000000 164.045000 0.390000 ;
    END
  END data_wdata_o[24]
  PIN data_wdata_o[23]
    DIRECTION OUTPUT ;
    USE SIGNAL ;
    PORT
      LAYER M2 ;
        RECT 166.495000 0.000000 166.565000 0.390000 ;
    END
  END data_wdata_o[23]
  PIN data_wdata_o[22]
    DIRECTION OUTPUT ;
    USE SIGNAL ;
    PORT
      LAYER M2 ;
        RECT 166.215000 0.000000 166.285000 0.390000 ;
    END
  END data_wdata_o[22]
  PIN data_wdata_o[21]
    DIRECTION OUTPUT ;
    USE SIGNAL ;
    PORT
      LAYER M2 ;
        RECT 164.675000 0.000000 164.745000 0.390000 ;
    END
  END data_wdata_o[21]
  PIN data_wdata_o[20]
    DIRECTION OUTPUT ;
    USE SIGNAL ;
    PORT
      LAYER M2 ;
        RECT 164.955000 0.000000 165.025000 0.390000 ;
    END
  END data_wdata_o[20]
  PIN data_wdata_o[19]
    DIRECTION OUTPUT ;
    USE SIGNAL ;
    PORT
      LAYER M2 ;
        RECT 162.575000 0.000000 162.645000 0.390000 ;
    END
  END data_wdata_o[19]
  PIN data_wdata_o[18]
    DIRECTION OUTPUT ;
    USE SIGNAL ;
    PORT
      LAYER M2 ;
        RECT 162.855000 0.000000 162.925000 0.390000 ;
    END
  END data_wdata_o[18]
  PIN data_wdata_o[17]
    DIRECTION OUTPUT ;
    USE SIGNAL ;
    PORT
      LAYER M2 ;
        RECT 161.035000 0.000000 161.105000 0.390000 ;
    END
  END data_wdata_o[17]
  PIN data_wdata_o[16]
    DIRECTION OUTPUT ;
    USE SIGNAL ;
    PORT
      LAYER M2 ;
        RECT 160.195000 0.000000 160.265000 0.390000 ;
    END
  END data_wdata_o[16]
  PIN data_wdata_o[15]
    DIRECTION OUTPUT ;
    USE SIGNAL ;
    PORT
      LAYER M2 ;
        RECT 159.215000 0.000000 159.285000 0.390000 ;
    END
  END data_wdata_o[15]
  PIN data_wdata_o[14]
    DIRECTION OUTPUT ;
    USE SIGNAL ;
    PORT
      LAYER M2 ;
        RECT 159.775000 0.000000 159.845000 0.390000 ;
    END
  END data_wdata_o[14]
  PIN data_wdata_o[13]
    DIRECTION OUTPUT ;
    USE SIGNAL ;
    PORT
      LAYER M2 ;
        RECT 165.935000 0.000000 166.005000 0.390000 ;
    END
  END data_wdata_o[13]
  PIN data_wdata_o[12]
    DIRECTION OUTPUT ;
    USE SIGNAL ;
    PORT
      LAYER M2 ;
        RECT 165.235000 0.000000 165.305000 0.390000 ;
    END
  END data_wdata_o[12]
  PIN data_wdata_o[11]
    DIRECTION OUTPUT ;
    USE SIGNAL ;
    PORT
      LAYER M2 ;
        RECT 163.695000 0.000000 163.765000 0.390000 ;
    END
  END data_wdata_o[11]
  PIN data_wdata_o[10]
    DIRECTION OUTPUT ;
    USE SIGNAL ;
    PORT
      LAYER M2 ;
        RECT 166.775000 0.000000 166.845000 0.390000 ;
    END
  END data_wdata_o[10]
  PIN data_wdata_o[9]
    DIRECTION OUTPUT ;
    USE SIGNAL ;
    PORT
      LAYER M2 ;
        RECT 163.135000 0.000000 163.205000 0.390000 ;
    END
  END data_wdata_o[9]
  PIN data_wdata_o[8]
    DIRECTION OUTPUT ;
    USE SIGNAL ;
    PORT
      LAYER M2 ;
        RECT 167.335000 0.000000 167.405000 0.390000 ;
    END
  END data_wdata_o[8]
  PIN data_wdata_o[7]
    DIRECTION OUTPUT ;
    USE SIGNAL ;
    PORT
      LAYER M2 ;
        RECT 163.415000 0.000000 163.485000 0.390000 ;
    END
  END data_wdata_o[7]
  PIN data_wdata_o[6]
    DIRECTION OUTPUT ;
    USE SIGNAL ;
    PORT
      LAYER M2 ;
        RECT 160.755000 0.000000 160.825000 0.390000 ;
    END
  END data_wdata_o[6]
  PIN data_wdata_o[5]
    DIRECTION OUTPUT ;
    USE SIGNAL ;
    PORT
      LAYER M2 ;
        RECT 167.615000 0.000000 167.685000 0.390000 ;
    END
  END data_wdata_o[5]
  PIN data_wdata_o[4]
    DIRECTION OUTPUT ;
    USE SIGNAL ;
    PORT
      LAYER M2 ;
        RECT 167.895000 0.000000 167.965000 0.390000 ;
    END
  END data_wdata_o[4]
  PIN data_wdata_o[3]
    DIRECTION OUTPUT ;
    USE SIGNAL ;
    PORT
      LAYER M2 ;
        RECT 160.475000 0.000000 160.545000 0.390000 ;
    END
  END data_wdata_o[3]
  PIN data_wdata_o[2]
    DIRECTION OUTPUT ;
    USE SIGNAL ;
    PORT
      LAYER M2 ;
        RECT 159.495000 0.000000 159.565000 0.390000 ;
    END
  END data_wdata_o[2]
  PIN data_wdata_o[1]
    DIRECTION OUTPUT ;
    USE SIGNAL ;
    PORT
      LAYER M2 ;
        RECT 158.935000 0.000000 159.005000 0.390000 ;
    END
  END data_wdata_o[1]
  PIN data_wdata_o[0]
    DIRECTION OUTPUT ;
    USE SIGNAL ;
    PORT
      LAYER M2 ;
        RECT 158.655000 0.000000 158.725000 0.390000 ;
    END
  END data_wdata_o[0]
  PIN data_rdata_i[31]
    DIRECTION INPUT ;
    USE SIGNAL ;
    PORT
      LAYER M2 ;
        RECT 154.175000 274.570000 154.245000 274.960000 ;
    END
  END data_rdata_i[31]
  PIN data_rdata_i[30]
    DIRECTION INPUT ;
    USE SIGNAL ;
    PORT
      LAYER M2 ;
        RECT 165.655000 274.570000 165.725000 274.960000 ;
    END
  END data_rdata_i[30]
  PIN data_rdata_i[29]
    DIRECTION INPUT ;
    USE SIGNAL ;
    PORT
      LAYER M2 ;
        RECT 171.675000 274.570000 171.745000 274.960000 ;
    END
  END data_rdata_i[29]
  PIN data_rdata_i[28]
    DIRECTION INPUT ;
    USE SIGNAL ;
    PORT
      LAYER M2 ;
        RECT 161.595000 274.570000 161.665000 274.960000 ;
    END
  END data_rdata_i[28]
  PIN data_rdata_i[27]
    DIRECTION INPUT ;
    USE SIGNAL ;
    PORT
      LAYER M2 ;
        RECT 158.795000 274.570000 158.865000 274.960000 ;
    END
  END data_rdata_i[27]
  PIN data_rdata_i[26]
    DIRECTION INPUT ;
    USE SIGNAL ;
    PORT
      LAYER M2 ;
        RECT 169.015000 274.570000 169.085000 274.960000 ;
    END
  END data_rdata_i[26]
  PIN data_rdata_i[25]
    DIRECTION INPUT ;
    USE SIGNAL ;
    PORT
      LAYER M2 ;
        RECT 155.155000 274.570000 155.225000 274.960000 ;
    END
  END data_rdata_i[25]
  PIN data_rdata_i[24]
    DIRECTION INPUT ;
    USE SIGNAL ;
    PORT
      LAYER M2 ;
        RECT 169.575000 274.570000 169.645000 274.960000 ;
    END
  END data_rdata_i[24]
  PIN data_rdata_i[23]
    DIRECTION INPUT ;
    USE SIGNAL ;
    PORT
      LAYER M2 ;
        RECT 153.195000 274.570000 153.265000 274.960000 ;
    END
  END data_rdata_i[23]
  PIN data_rdata_i[22]
    DIRECTION INPUT ;
    USE SIGNAL ;
    PORT
      LAYER M2 ;
        RECT 164.675000 274.570000 164.745000 274.960000 ;
    END
  END data_rdata_i[22]
  PIN data_rdata_i[21]
    DIRECTION INPUT ;
    USE SIGNAL ;
    PORT
      LAYER M2 ;
        RECT 169.295000 274.570000 169.365000 274.960000 ;
    END
  END data_rdata_i[21]
  PIN data_rdata_i[20]
    DIRECTION INPUT ;
    USE SIGNAL ;
    PORT
      LAYER M2 ;
        RECT 162.575000 274.570000 162.645000 274.960000 ;
    END
  END data_rdata_i[20]
  PIN data_rdata_i[19]
    DIRECTION INPUT ;
    USE SIGNAL ;
    PORT
      LAYER M2 ;
        RECT 158.515000 274.570000 158.585000 274.960000 ;
    END
  END data_rdata_i[19]
  PIN data_rdata_i[18]
    DIRECTION INPUT ;
    USE SIGNAL ;
    PORT
      LAYER M2 ;
        RECT 168.735000 274.570000 168.805000 274.960000 ;
    END
  END data_rdata_i[18]
  PIN data_rdata_i[17]
    DIRECTION INPUT ;
    USE SIGNAL ;
    PORT
      LAYER M2 ;
        RECT 156.975000 274.570000 157.045000 274.960000 ;
    END
  END data_rdata_i[17]
  PIN data_rdata_i[16]
    DIRECTION INPUT ;
    USE SIGNAL ;
    PORT
      LAYER M2 ;
        RECT 170.275000 274.570000 170.345000 274.960000 ;
    END
  END data_rdata_i[16]
  PIN data_rdata_i[15]
    DIRECTION INPUT ;
    USE SIGNAL ;
    PORT
      LAYER M2 ;
        RECT 154.595000 274.570000 154.665000 274.960000 ;
    END
  END data_rdata_i[15]
  PIN data_rdata_i[14]
    DIRECTION INPUT ;
    USE SIGNAL ;
    PORT
      LAYER M2 ;
        RECT 165.235000 274.570000 165.305000 274.960000 ;
    END
  END data_rdata_i[14]
  PIN data_rdata_i[13]
    DIRECTION INPUT ;
    USE SIGNAL ;
    PORT
      LAYER M2 ;
        RECT 171.395000 274.570000 171.465000 274.960000 ;
    END
  END data_rdata_i[13]
  PIN data_rdata_i[12]
    DIRECTION INPUT ;
    USE SIGNAL ;
    PORT
      LAYER M2 ;
        RECT 162.855000 274.570000 162.925000 274.960000 ;
    END
  END data_rdata_i[12]
  PIN data_rdata_i[11]
    DIRECTION INPUT ;
    USE SIGNAL ;
    PORT
      LAYER M2 ;
        RECT 157.255000 274.570000 157.325000 274.960000 ;
    END
  END data_rdata_i[11]
  PIN data_rdata_i[10]
    DIRECTION INPUT ;
    USE SIGNAL ;
    PORT
      LAYER M2 ;
        RECT 169.995000 274.570000 170.065000 274.960000 ;
    END
  END data_rdata_i[10]
  PIN data_rdata_i[9]
    DIRECTION INPUT ;
    USE SIGNAL ;
    PORT
      LAYER M2 ;
        RECT 155.995000 274.570000 156.065000 274.960000 ;
    END
  END data_rdata_i[9]
  PIN data_rdata_i[8]
    DIRECTION INPUT ;
    USE SIGNAL ;
    PORT
      LAYER M2 ;
        RECT 171.955000 274.570000 172.025000 274.960000 ;
    END
  END data_rdata_i[8]
  PIN data_rdata_i[7]
    DIRECTION INPUT ;
    USE SIGNAL ;
    PORT
      LAYER M2 ;
        RECT 156.555000 274.570000 156.625000 274.960000 ;
    END
  END data_rdata_i[7]
  PIN data_rdata_i[6]
    DIRECTION INPUT ;
    USE SIGNAL ;
    PORT
      LAYER M2 ;
        RECT 166.915000 274.570000 166.985000 274.960000 ;
    END
  END data_rdata_i[6]
  PIN data_rdata_i[5]
    DIRECTION INPUT ;
    USE SIGNAL ;
    PORT
      LAYER M2 ;
        RECT 172.375000 274.570000 172.445000 274.960000 ;
    END
  END data_rdata_i[5]
  PIN data_rdata_i[4]
    DIRECTION INPUT ;
    USE SIGNAL ;
    PORT
      LAYER M2 ;
        RECT 162.015000 274.570000 162.085000 274.960000 ;
    END
  END data_rdata_i[4]
  PIN data_rdata_i[3]
    DIRECTION INPUT ;
    USE SIGNAL ;
    PORT
      LAYER M2 ;
        RECT 158.095000 274.570000 158.165000 274.960000 ;
    END
  END data_rdata_i[3]
  PIN data_rdata_i[2]
    DIRECTION INPUT ;
    USE SIGNAL ;
    PORT
      LAYER M2 ;
        RECT 170.555000 274.570000 170.625000 274.960000 ;
    END
  END data_rdata_i[2]
  PIN data_rdata_i[1]
    DIRECTION INPUT ;
    USE SIGNAL ;
    PORT
      LAYER M2 ;
        RECT 155.435000 274.570000 155.505000 274.960000 ;
    END
  END data_rdata_i[1]
  PIN data_rdata_i[0]
    DIRECTION INPUT ;
    USE SIGNAL ;
    PORT
      LAYER M2 ;
        RECT 170.975000 274.570000 171.045000 274.960000 ;
    END
  END data_rdata_i[0]
  PIN data_err_i
    DIRECTION INPUT ;
    USE SIGNAL ;
    PORT
      LAYER M2 ;
        RECT 146.195000 274.570000 146.265000 274.960000 ;
    END
  END data_err_i
  PIN irq_software_i
    DIRECTION INPUT ;
    USE SIGNAL ;
    PORT
      LAYER M2 ;
        RECT 74.935000 274.570000 75.005000 274.960000 ;
    END
  END irq_software_i
  PIN irq_timer_i
    DIRECTION INPUT ;
    USE SIGNAL ;
    PORT
      LAYER M2 ;
        RECT 78.855000 274.570000 78.925000 274.960000 ;
    END
  END irq_timer_i
  PIN irq_external_i
    DIRECTION INPUT ;
    USE SIGNAL ;
    PORT
      LAYER M2 ;
        RECT 83.055000 274.570000 83.125000 274.960000 ;
    END
  END irq_external_i
  PIN irq_fast_i[14]
    DIRECTION INPUT ;
    USE SIGNAL ;
    PORT
      LAYER M2 ;
        RECT 98.875000 274.570000 98.945000 274.960000 ;
    END
  END irq_fast_i[14]
  PIN irq_fast_i[13]
    DIRECTION INPUT ;
    USE SIGNAL ;
    PORT
      LAYER M2 ;
        RECT 117.915000 274.570000 117.985000 274.960000 ;
    END
  END irq_fast_i[13]
  PIN irq_fast_i[12]
    DIRECTION INPUT ;
    USE SIGNAL ;
    PORT
      LAYER M2 ;
        RECT 130.655000 274.570000 130.725000 274.960000 ;
    END
  END irq_fast_i[12]
  PIN irq_fast_i[11]
    DIRECTION INPUT ;
    USE SIGNAL ;
    PORT
      LAYER M2 ;
        RECT 135.415000 274.570000 135.485000 274.960000 ;
    END
  END irq_fast_i[11]
  PIN irq_fast_i[10]
    DIRECTION INPUT ;
    USE SIGNAL ;
    PORT
      LAYER M2 ;
        RECT 136.115000 274.570000 136.185000 274.960000 ;
    END
  END irq_fast_i[10]
  PIN irq_fast_i[9]
    DIRECTION INPUT ;
    USE SIGNAL ;
    PORT
      LAYER M2 ;
        RECT 140.175000 274.570000 140.245000 274.960000 ;
    END
  END irq_fast_i[9]
  PIN irq_fast_i[8]
    DIRECTION INPUT ;
    USE SIGNAL ;
    PORT
      LAYER M2 ;
        RECT 141.435000 274.570000 141.505000 274.960000 ;
    END
  END irq_fast_i[8]
  PIN irq_fast_i[7]
    DIRECTION INPUT ;
    USE SIGNAL ;
    PORT
      LAYER M2 ;
        RECT 139.615000 274.570000 139.685000 274.960000 ;
    END
  END irq_fast_i[7]
  PIN irq_fast_i[6]
    DIRECTION INPUT ;
    USE SIGNAL ;
    PORT
      LAYER M2 ;
        RECT 137.235000 274.570000 137.305000 274.960000 ;
    END
  END irq_fast_i[6]
  PIN irq_fast_i[5]
    DIRECTION INPUT ;
    USE SIGNAL ;
    PORT
      LAYER M2 ;
        RECT 111.335000 274.570000 111.405000 274.960000 ;
    END
  END irq_fast_i[5]
  PIN irq_fast_i[4]
    DIRECTION INPUT ;
    USE SIGNAL ;
    PORT
      LAYER M2 ;
        RECT 111.615000 274.570000 111.685000 274.960000 ;
    END
  END irq_fast_i[4]
  PIN irq_fast_i[3]
    DIRECTION INPUT ;
    USE SIGNAL ;
    PORT
      LAYER M2 ;
        RECT 120.715000 274.570000 120.785000 274.960000 ;
    END
  END irq_fast_i[3]
  PIN irq_fast_i[2]
    DIRECTION INPUT ;
    USE SIGNAL ;
    PORT
      LAYER M2 ;
        RECT 124.495000 274.570000 124.565000 274.960000 ;
    END
  END irq_fast_i[2]
  PIN irq_fast_i[1]
    DIRECTION INPUT ;
    USE SIGNAL ;
    PORT
      LAYER M2 ;
        RECT 112.735000 274.570000 112.805000 274.960000 ;
    END
  END irq_fast_i[1]
  PIN irq_fast_i[0]
    DIRECTION INPUT ;
    USE SIGNAL ;
    PORT
      LAYER M2 ;
        RECT 127.015000 274.570000 127.085000 274.960000 ;
    END
  END irq_fast_i[0]
  PIN irq_nm_i
    DIRECTION INPUT ;
    USE SIGNAL ;
    PORT
      LAYER M3 ;
        RECT 0.000000 177.905000 0.390000 177.975000 ;
    END
  END irq_nm_i
  PIN debug_req_i
    DIRECTION INPUT ;
    USE SIGNAL ;
    PORT
      LAYER M3 ;
        RECT 0.000000 167.545000 0.390000 167.615000 ;
    END
  END debug_req_i
  PIN fetch_enable_i
    DIRECTION INPUT ;
    USE SIGNAL ;
    PORT
      LAYER M3 ;
        RECT 0.000000 163.765000 0.390000 163.835000 ;
    END
  END fetch_enable_i
  PIN alert_minor_o
    DIRECTION OUTPUT ;
    USE SIGNAL ;
    PORT
      LAYER M3 ;
        RECT 0.000000 137.305000 0.390000 137.375000 ;
    END
  END alert_minor_o
  PIN alert_major_o
    DIRECTION OUTPUT ;
    USE SIGNAL ;
    PORT
      LAYER M2 ;
        RECT 149.135000 274.570000 149.205000 274.960000 ;
    END
  END alert_major_o
  PIN core_sleep_o
    DIRECTION OUTPUT ;
    USE SIGNAL ;
    PORT
      LAYER M3 ;
        RECT 0.000000 165.585000 0.390000 165.655000 ;
    END
  END core_sleep_o
  PIN VSS
    DIRECTION INOUT ;
    USE GROUND ;

# P/G power stripe data as pin
    PORT
      LAYER M3 ;
        RECT 1.980000 137.405000 6.180000 137.835000 ;
        RECT 47.330000 137.405000 47.680000 137.835000 ;
        RECT 87.330000 137.405000 87.680000 137.835000 ;
        RECT 127.330000 137.405000 127.680000 137.835000 ;
        RECT 167.330000 137.405000 167.680000 137.835000 ;
        RECT 207.330000 137.405000 207.680000 137.835000 ;
        RECT 247.330000 137.405000 247.680000 137.835000 ;
        RECT 293.840000 137.405000 298.040000 137.835000 ;
        RECT 1.980000 19.805000 6.180000 20.235000 ;
        RECT 1.980000 16.445000 6.180000 16.875000 ;
        RECT 1.980000 23.165000 6.180000 23.595000 ;
        RECT 47.330000 19.805000 47.680000 20.235000 ;
        RECT 47.330000 23.165000 47.680000 23.595000 ;
        RECT 47.330000 16.445000 47.680000 16.875000 ;
        RECT 1.980000 43.325000 6.180000 43.755000 ;
        RECT 1.980000 26.525000 6.180000 26.955000 ;
        RECT 1.980000 29.885000 6.180000 30.315000 ;
        RECT 1.980000 33.245000 6.180000 33.675000 ;
        RECT 1.980000 36.605000 6.180000 37.035000 ;
        RECT 1.980000 39.965000 6.180000 40.395000 ;
        RECT 1.980000 46.685000 6.180000 47.115000 ;
        RECT 1.980000 50.045000 6.180000 50.475000 ;
        RECT 1.980000 60.125000 6.180000 60.555000 ;
        RECT 1.980000 53.405000 6.180000 53.835000 ;
        RECT 1.980000 56.765000 6.180000 57.195000 ;
        RECT 47.330000 43.325000 47.680000 43.755000 ;
        RECT 47.330000 26.525000 47.680000 26.955000 ;
        RECT 47.330000 29.885000 47.680000 30.315000 ;
        RECT 47.330000 33.245000 47.680000 33.675000 ;
        RECT 47.330000 36.605000 47.680000 37.035000 ;
        RECT 47.330000 39.965000 47.680000 40.395000 ;
        RECT 47.330000 46.685000 47.680000 47.115000 ;
        RECT 47.330000 50.045000 47.680000 50.475000 ;
        RECT 47.330000 60.125000 47.680000 60.555000 ;
        RECT 47.330000 56.765000 47.680000 57.195000 ;
        RECT 47.330000 53.405000 47.680000 53.835000 ;
        RECT 87.330000 23.165000 87.680000 23.595000 ;
        RECT 87.330000 19.805000 87.680000 20.235000 ;
        RECT 87.330000 16.445000 87.680000 16.875000 ;
        RECT 127.330000 23.165000 127.680000 23.595000 ;
        RECT 127.330000 19.805000 127.680000 20.235000 ;
        RECT 127.330000 16.445000 127.680000 16.875000 ;
        RECT 87.330000 43.325000 87.680000 43.755000 ;
        RECT 87.330000 26.525000 87.680000 26.955000 ;
        RECT 87.330000 29.885000 87.680000 30.315000 ;
        RECT 87.330000 33.245000 87.680000 33.675000 ;
        RECT 87.330000 36.605000 87.680000 37.035000 ;
        RECT 87.330000 39.965000 87.680000 40.395000 ;
        RECT 87.330000 46.685000 87.680000 47.115000 ;
        RECT 87.330000 50.045000 87.680000 50.475000 ;
        RECT 87.330000 60.125000 87.680000 60.555000 ;
        RECT 87.330000 56.765000 87.680000 57.195000 ;
        RECT 87.330000 53.405000 87.680000 53.835000 ;
        RECT 127.330000 43.325000 127.680000 43.755000 ;
        RECT 127.330000 26.525000 127.680000 26.955000 ;
        RECT 127.330000 29.885000 127.680000 30.315000 ;
        RECT 127.330000 33.245000 127.680000 33.675000 ;
        RECT 127.330000 36.605000 127.680000 37.035000 ;
        RECT 127.330000 39.965000 127.680000 40.395000 ;
        RECT 127.330000 46.685000 127.680000 47.115000 ;
        RECT 127.330000 50.045000 127.680000 50.475000 ;
        RECT 127.330000 60.125000 127.680000 60.555000 ;
        RECT 127.330000 56.765000 127.680000 57.195000 ;
        RECT 127.330000 53.405000 127.680000 53.835000 ;
        RECT 1.980000 63.485000 6.180000 63.915000 ;
        RECT 1.980000 66.845000 6.180000 67.275000 ;
        RECT 1.980000 70.205000 6.180000 70.635000 ;
        RECT 1.980000 80.285000 6.180000 80.715000 ;
        RECT 1.980000 73.565000 6.180000 73.995000 ;
        RECT 1.980000 76.925000 6.180000 77.355000 ;
        RECT 1.980000 90.365000 6.180000 90.795000 ;
        RECT 1.980000 83.645000 6.180000 84.075000 ;
        RECT 1.980000 87.005000 6.180000 87.435000 ;
        RECT 1.980000 93.725000 6.180000 94.155000 ;
        RECT 1.980000 97.085000 6.180000 97.515000 ;
        RECT 47.330000 63.485000 47.680000 63.915000 ;
        RECT 47.330000 66.845000 47.680000 67.275000 ;
        RECT 47.330000 70.205000 47.680000 70.635000 ;
        RECT 47.330000 80.285000 47.680000 80.715000 ;
        RECT 47.330000 76.925000 47.680000 77.355000 ;
        RECT 47.330000 73.565000 47.680000 73.995000 ;
        RECT 47.330000 90.365000 47.680000 90.795000 ;
        RECT 47.330000 83.645000 47.680000 84.075000 ;
        RECT 47.330000 87.005000 47.680000 87.435000 ;
        RECT 47.330000 93.725000 47.680000 94.155000 ;
        RECT 47.330000 97.085000 47.680000 97.515000 ;
        RECT 1.980000 107.165000 6.180000 107.595000 ;
        RECT 1.980000 100.445000 6.180000 100.875000 ;
        RECT 1.980000 103.805000 6.180000 104.235000 ;
        RECT 1.980000 110.525000 6.180000 110.955000 ;
        RECT 1.980000 113.885000 6.180000 114.315000 ;
        RECT 1.980000 117.245000 6.180000 117.675000 ;
        RECT 1.980000 127.325000 6.180000 127.755000 ;
        RECT 1.980000 120.605000 6.180000 121.035000 ;
        RECT 1.980000 123.965000 6.180000 124.395000 ;
        RECT 1.980000 130.685000 6.180000 131.115000 ;
        RECT 1.980000 134.045000 6.180000 134.475000 ;
        RECT 47.330000 107.165000 47.680000 107.595000 ;
        RECT 47.330000 103.805000 47.680000 104.235000 ;
        RECT 47.330000 100.445000 47.680000 100.875000 ;
        RECT 47.330000 110.525000 47.680000 110.955000 ;
        RECT 47.330000 113.885000 47.680000 114.315000 ;
        RECT 47.330000 117.245000 47.680000 117.675000 ;
        RECT 47.330000 127.325000 47.680000 127.755000 ;
        RECT 47.330000 123.965000 47.680000 124.395000 ;
        RECT 47.330000 120.605000 47.680000 121.035000 ;
        RECT 47.330000 130.685000 47.680000 131.115000 ;
        RECT 47.330000 134.045000 47.680000 134.475000 ;
        RECT 87.330000 63.485000 87.680000 63.915000 ;
        RECT 87.330000 66.845000 87.680000 67.275000 ;
        RECT 87.330000 70.205000 87.680000 70.635000 ;
        RECT 87.330000 73.565000 87.680000 73.995000 ;
        RECT 87.330000 76.925000 87.680000 77.355000 ;
        RECT 87.330000 80.285000 87.680000 80.715000 ;
        RECT 87.330000 90.365000 87.680000 90.795000 ;
        RECT 87.330000 83.645000 87.680000 84.075000 ;
        RECT 87.330000 87.005000 87.680000 87.435000 ;
        RECT 87.330000 93.725000 87.680000 94.155000 ;
        RECT 87.330000 97.085000 87.680000 97.515000 ;
        RECT 127.330000 63.485000 127.680000 63.915000 ;
        RECT 127.330000 66.845000 127.680000 67.275000 ;
        RECT 127.330000 70.205000 127.680000 70.635000 ;
        RECT 127.330000 73.565000 127.680000 73.995000 ;
        RECT 127.330000 76.925000 127.680000 77.355000 ;
        RECT 127.330000 80.285000 127.680000 80.715000 ;
        RECT 127.330000 90.365000 127.680000 90.795000 ;
        RECT 127.330000 83.645000 127.680000 84.075000 ;
        RECT 127.330000 87.005000 127.680000 87.435000 ;
        RECT 127.330000 93.725000 127.680000 94.155000 ;
        RECT 127.330000 97.085000 127.680000 97.515000 ;
        RECT 87.330000 107.165000 87.680000 107.595000 ;
        RECT 87.330000 103.805000 87.680000 104.235000 ;
        RECT 87.330000 100.445000 87.680000 100.875000 ;
        RECT 87.330000 110.525000 87.680000 110.955000 ;
        RECT 87.330000 113.885000 87.680000 114.315000 ;
        RECT 87.330000 117.245000 87.680000 117.675000 ;
        RECT 87.330000 127.325000 87.680000 127.755000 ;
        RECT 87.330000 123.965000 87.680000 124.395000 ;
        RECT 87.330000 120.605000 87.680000 121.035000 ;
        RECT 87.330000 130.685000 87.680000 131.115000 ;
        RECT 87.330000 134.045000 87.680000 134.475000 ;
        RECT 127.330000 107.165000 127.680000 107.595000 ;
        RECT 127.330000 103.805000 127.680000 104.235000 ;
        RECT 127.330000 100.445000 127.680000 100.875000 ;
        RECT 127.330000 113.885000 127.680000 114.315000 ;
        RECT 127.330000 110.525000 127.680000 110.955000 ;
        RECT 127.330000 117.245000 127.680000 117.675000 ;
        RECT 127.330000 127.325000 127.680000 127.755000 ;
        RECT 127.330000 123.965000 127.680000 124.395000 ;
        RECT 127.330000 120.605000 127.680000 121.035000 ;
        RECT 127.330000 130.685000 127.680000 131.115000 ;
        RECT 127.330000 134.045000 127.680000 134.475000 ;
        RECT 167.330000 23.165000 167.680000 23.595000 ;
        RECT 167.330000 19.805000 167.680000 20.235000 ;
        RECT 167.330000 16.445000 167.680000 16.875000 ;
        RECT 207.330000 16.445000 207.680000 16.875000 ;
        RECT 207.330000 19.805000 207.680000 20.235000 ;
        RECT 207.330000 23.165000 207.680000 23.595000 ;
        RECT 167.330000 43.325000 167.680000 43.755000 ;
        RECT 167.330000 26.525000 167.680000 26.955000 ;
        RECT 167.330000 29.885000 167.680000 30.315000 ;
        RECT 167.330000 33.245000 167.680000 33.675000 ;
        RECT 167.330000 36.605000 167.680000 37.035000 ;
        RECT 167.330000 39.965000 167.680000 40.395000 ;
        RECT 167.330000 46.685000 167.680000 47.115000 ;
        RECT 167.330000 50.045000 167.680000 50.475000 ;
        RECT 167.330000 53.405000 167.680000 53.835000 ;
        RECT 167.330000 56.765000 167.680000 57.195000 ;
        RECT 167.330000 60.125000 167.680000 60.555000 ;
        RECT 207.330000 43.325000 207.680000 43.755000 ;
        RECT 207.330000 26.525000 207.680000 26.955000 ;
        RECT 207.330000 29.885000 207.680000 30.315000 ;
        RECT 207.330000 33.245000 207.680000 33.675000 ;
        RECT 207.330000 36.605000 207.680000 37.035000 ;
        RECT 207.330000 39.965000 207.680000 40.395000 ;
        RECT 207.330000 46.685000 207.680000 47.115000 ;
        RECT 207.330000 50.045000 207.680000 50.475000 ;
        RECT 207.330000 53.405000 207.680000 53.835000 ;
        RECT 207.330000 56.765000 207.680000 57.195000 ;
        RECT 207.330000 60.125000 207.680000 60.555000 ;
        RECT 247.330000 19.805000 247.680000 20.235000 ;
        RECT 247.330000 23.165000 247.680000 23.595000 ;
        RECT 247.330000 16.445000 247.680000 16.875000 ;
        RECT 293.840000 19.805000 298.040000 20.235000 ;
        RECT 293.840000 16.445000 298.040000 16.875000 ;
        RECT 293.840000 23.165000 298.040000 23.595000 ;
        RECT 247.330000 43.325000 247.680000 43.755000 ;
        RECT 247.330000 26.525000 247.680000 26.955000 ;
        RECT 247.330000 29.885000 247.680000 30.315000 ;
        RECT 247.330000 33.245000 247.680000 33.675000 ;
        RECT 247.330000 36.605000 247.680000 37.035000 ;
        RECT 247.330000 39.965000 247.680000 40.395000 ;
        RECT 247.330000 46.685000 247.680000 47.115000 ;
        RECT 247.330000 50.045000 247.680000 50.475000 ;
        RECT 247.330000 53.405000 247.680000 53.835000 ;
        RECT 247.330000 56.765000 247.680000 57.195000 ;
        RECT 247.330000 60.125000 247.680000 60.555000 ;
        RECT 293.840000 43.325000 298.040000 43.755000 ;
        RECT 293.840000 26.525000 298.040000 26.955000 ;
        RECT 293.840000 29.885000 298.040000 30.315000 ;
        RECT 293.840000 33.245000 298.040000 33.675000 ;
        RECT 293.840000 36.605000 298.040000 37.035000 ;
        RECT 293.840000 39.965000 298.040000 40.395000 ;
        RECT 293.840000 46.685000 298.040000 47.115000 ;
        RECT 293.840000 50.045000 298.040000 50.475000 ;
        RECT 293.840000 60.125000 298.040000 60.555000 ;
        RECT 293.840000 53.405000 298.040000 53.835000 ;
        RECT 293.840000 56.765000 298.040000 57.195000 ;
        RECT 167.330000 66.845000 167.680000 67.275000 ;
        RECT 167.330000 63.485000 167.680000 63.915000 ;
        RECT 167.330000 70.205000 167.680000 70.635000 ;
        RECT 167.330000 73.565000 167.680000 73.995000 ;
        RECT 167.330000 76.925000 167.680000 77.355000 ;
        RECT 167.330000 80.285000 167.680000 80.715000 ;
        RECT 167.330000 90.365000 167.680000 90.795000 ;
        RECT 167.330000 83.645000 167.680000 84.075000 ;
        RECT 167.330000 87.005000 167.680000 87.435000 ;
        RECT 167.330000 93.725000 167.680000 94.155000 ;
        RECT 167.330000 97.085000 167.680000 97.515000 ;
        RECT 207.330000 66.845000 207.680000 67.275000 ;
        RECT 207.330000 63.485000 207.680000 63.915000 ;
        RECT 207.330000 70.205000 207.680000 70.635000 ;
        RECT 207.330000 80.285000 207.680000 80.715000 ;
        RECT 207.330000 76.925000 207.680000 77.355000 ;
        RECT 207.330000 73.565000 207.680000 73.995000 ;
        RECT 207.330000 90.365000 207.680000 90.795000 ;
        RECT 207.330000 83.645000 207.680000 84.075000 ;
        RECT 207.330000 87.005000 207.680000 87.435000 ;
        RECT 207.330000 93.725000 207.680000 94.155000 ;
        RECT 207.330000 97.085000 207.680000 97.515000 ;
        RECT 167.330000 107.165000 167.680000 107.595000 ;
        RECT 167.330000 103.805000 167.680000 104.235000 ;
        RECT 167.330000 100.445000 167.680000 100.875000 ;
        RECT 167.330000 110.525000 167.680000 110.955000 ;
        RECT 167.330000 113.885000 167.680000 114.315000 ;
        RECT 167.330000 117.245000 167.680000 117.675000 ;
        RECT 167.330000 127.325000 167.680000 127.755000 ;
        RECT 167.330000 123.965000 167.680000 124.395000 ;
        RECT 167.330000 120.605000 167.680000 121.035000 ;
        RECT 167.330000 134.045000 167.680000 134.475000 ;
        RECT 167.330000 130.685000 167.680000 131.115000 ;
        RECT 207.330000 107.165000 207.680000 107.595000 ;
        RECT 207.330000 103.805000 207.680000 104.235000 ;
        RECT 207.330000 100.445000 207.680000 100.875000 ;
        RECT 207.330000 113.885000 207.680000 114.315000 ;
        RECT 207.330000 110.525000 207.680000 110.955000 ;
        RECT 207.330000 117.245000 207.680000 117.675000 ;
        RECT 207.330000 120.605000 207.680000 121.035000 ;
        RECT 207.330000 123.965000 207.680000 124.395000 ;
        RECT 207.330000 127.325000 207.680000 127.755000 ;
        RECT 207.330000 134.045000 207.680000 134.475000 ;
        RECT 207.330000 130.685000 207.680000 131.115000 ;
        RECT 247.330000 66.845000 247.680000 67.275000 ;
        RECT 247.330000 63.485000 247.680000 63.915000 ;
        RECT 247.330000 70.205000 247.680000 70.635000 ;
        RECT 247.330000 73.565000 247.680000 73.995000 ;
        RECT 247.330000 76.925000 247.680000 77.355000 ;
        RECT 247.330000 80.285000 247.680000 80.715000 ;
        RECT 247.330000 90.365000 247.680000 90.795000 ;
        RECT 247.330000 83.645000 247.680000 84.075000 ;
        RECT 247.330000 87.005000 247.680000 87.435000 ;
        RECT 247.330000 93.725000 247.680000 94.155000 ;
        RECT 247.330000 97.085000 247.680000 97.515000 ;
        RECT 293.840000 63.485000 298.040000 63.915000 ;
        RECT 293.840000 66.845000 298.040000 67.275000 ;
        RECT 293.840000 70.205000 298.040000 70.635000 ;
        RECT 293.840000 80.285000 298.040000 80.715000 ;
        RECT 293.840000 73.565000 298.040000 73.995000 ;
        RECT 293.840000 76.925000 298.040000 77.355000 ;
        RECT 293.840000 90.365000 298.040000 90.795000 ;
        RECT 293.840000 83.645000 298.040000 84.075000 ;
        RECT 293.840000 87.005000 298.040000 87.435000 ;
        RECT 293.840000 93.725000 298.040000 94.155000 ;
        RECT 293.840000 97.085000 298.040000 97.515000 ;
        RECT 247.330000 100.445000 247.680000 100.875000 ;
        RECT 247.330000 103.805000 247.680000 104.235000 ;
        RECT 247.330000 107.165000 247.680000 107.595000 ;
        RECT 247.330000 113.885000 247.680000 114.315000 ;
        RECT 247.330000 110.525000 247.680000 110.955000 ;
        RECT 247.330000 117.245000 247.680000 117.675000 ;
        RECT 247.330000 127.325000 247.680000 127.755000 ;
        RECT 247.330000 123.965000 247.680000 124.395000 ;
        RECT 247.330000 120.605000 247.680000 121.035000 ;
        RECT 247.330000 130.685000 247.680000 131.115000 ;
        RECT 247.330000 134.045000 247.680000 134.475000 ;
        RECT 293.840000 107.165000 298.040000 107.595000 ;
        RECT 293.840000 100.445000 298.040000 100.875000 ;
        RECT 293.840000 103.805000 298.040000 104.235000 ;
        RECT 293.840000 110.525000 298.040000 110.955000 ;
        RECT 293.840000 113.885000 298.040000 114.315000 ;
        RECT 293.840000 117.245000 298.040000 117.675000 ;
        RECT 293.840000 127.325000 298.040000 127.755000 ;
        RECT 293.840000 120.605000 298.040000 121.035000 ;
        RECT 293.840000 123.965000 298.040000 124.395000 ;
        RECT 293.840000 130.685000 298.040000 131.115000 ;
        RECT 293.840000 134.045000 298.040000 134.475000 ;
        RECT 1.980000 140.765000 6.180000 141.195000 ;
        RECT 1.980000 144.125000 6.180000 144.555000 ;
        RECT 1.980000 147.485000 6.180000 147.915000 ;
        RECT 1.980000 150.845000 6.180000 151.275000 ;
        RECT 1.980000 154.205000 6.180000 154.635000 ;
        RECT 1.980000 157.565000 6.180000 157.995000 ;
        RECT 1.980000 160.925000 6.180000 161.355000 ;
        RECT 1.980000 164.285000 6.180000 164.715000 ;
        RECT 1.980000 174.365000 6.180000 174.795000 ;
        RECT 1.980000 167.645000 6.180000 168.075000 ;
        RECT 1.980000 171.005000 6.180000 171.435000 ;
        RECT 47.330000 144.125000 47.680000 144.555000 ;
        RECT 47.330000 140.765000 47.680000 141.195000 ;
        RECT 47.330000 147.485000 47.680000 147.915000 ;
        RECT 47.330000 150.845000 47.680000 151.275000 ;
        RECT 47.330000 154.205000 47.680000 154.635000 ;
        RECT 47.330000 157.565000 47.680000 157.995000 ;
        RECT 47.330000 160.925000 47.680000 161.355000 ;
        RECT 47.330000 164.285000 47.680000 164.715000 ;
        RECT 47.330000 174.365000 47.680000 174.795000 ;
        RECT 47.330000 171.005000 47.680000 171.435000 ;
        RECT 47.330000 167.645000 47.680000 168.075000 ;
        RECT 1.980000 177.725000 6.180000 178.155000 ;
        RECT 1.980000 181.085000 6.180000 181.515000 ;
        RECT 1.980000 191.165000 6.180000 191.595000 ;
        RECT 1.980000 184.445000 6.180000 184.875000 ;
        RECT 1.980000 187.805000 6.180000 188.235000 ;
        RECT 1.980000 194.525000 6.180000 194.955000 ;
        RECT 1.980000 197.885000 6.180000 198.315000 ;
        RECT 1.980000 201.245000 6.180000 201.675000 ;
        RECT 1.980000 204.605000 6.180000 205.035000 ;
        RECT 1.980000 207.965000 6.180000 208.395000 ;
        RECT 1.980000 211.325000 6.180000 211.755000 ;
        RECT 47.330000 177.725000 47.680000 178.155000 ;
        RECT 47.330000 181.085000 47.680000 181.515000 ;
        RECT 47.330000 184.445000 47.680000 184.875000 ;
        RECT 47.330000 187.805000 47.680000 188.235000 ;
        RECT 47.330000 191.165000 47.680000 191.595000 ;
        RECT 47.330000 201.245000 47.680000 201.675000 ;
        RECT 47.330000 197.885000 47.680000 198.315000 ;
        RECT 47.330000 194.525000 47.680000 194.955000 ;
        RECT 47.330000 204.605000 47.680000 205.035000 ;
        RECT 47.330000 207.965000 47.680000 208.395000 ;
        RECT 47.330000 211.325000 47.680000 211.755000 ;
        RECT 87.330000 140.765000 87.680000 141.195000 ;
        RECT 87.330000 144.125000 87.680000 144.555000 ;
        RECT 87.330000 147.485000 87.680000 147.915000 ;
        RECT 87.330000 150.845000 87.680000 151.275000 ;
        RECT 87.330000 154.205000 87.680000 154.635000 ;
        RECT 87.330000 164.285000 87.680000 164.715000 ;
        RECT 87.330000 160.925000 87.680000 161.355000 ;
        RECT 87.330000 157.565000 87.680000 157.995000 ;
        RECT 87.330000 174.365000 87.680000 174.795000 ;
        RECT 87.330000 171.005000 87.680000 171.435000 ;
        RECT 87.330000 167.645000 87.680000 168.075000 ;
        RECT 127.330000 140.765000 127.680000 141.195000 ;
        RECT 127.330000 144.125000 127.680000 144.555000 ;
        RECT 127.330000 147.485000 127.680000 147.915000 ;
        RECT 127.330000 150.845000 127.680000 151.275000 ;
        RECT 127.330000 154.205000 127.680000 154.635000 ;
        RECT 127.330000 157.565000 127.680000 157.995000 ;
        RECT 127.330000 160.925000 127.680000 161.355000 ;
        RECT 127.330000 164.285000 127.680000 164.715000 ;
        RECT 127.330000 174.365000 127.680000 174.795000 ;
        RECT 127.330000 171.005000 127.680000 171.435000 ;
        RECT 127.330000 167.645000 127.680000 168.075000 ;
        RECT 87.330000 181.085000 87.680000 181.515000 ;
        RECT 87.330000 177.725000 87.680000 178.155000 ;
        RECT 87.330000 184.445000 87.680000 184.875000 ;
        RECT 87.330000 187.805000 87.680000 188.235000 ;
        RECT 87.330000 191.165000 87.680000 191.595000 ;
        RECT 87.330000 194.525000 87.680000 194.955000 ;
        RECT 87.330000 197.885000 87.680000 198.315000 ;
        RECT 87.330000 201.245000 87.680000 201.675000 ;
        RECT 87.330000 204.605000 87.680000 205.035000 ;
        RECT 87.330000 207.965000 87.680000 208.395000 ;
        RECT 87.330000 211.325000 87.680000 211.755000 ;
        RECT 127.330000 177.725000 127.680000 178.155000 ;
        RECT 127.330000 181.085000 127.680000 181.515000 ;
        RECT 127.330000 184.445000 127.680000 184.875000 ;
        RECT 127.330000 187.805000 127.680000 188.235000 ;
        RECT 127.330000 191.165000 127.680000 191.595000 ;
        RECT 127.330000 194.525000 127.680000 194.955000 ;
        RECT 127.330000 197.885000 127.680000 198.315000 ;
        RECT 127.330000 201.245000 127.680000 201.675000 ;
        RECT 127.330000 204.605000 127.680000 205.035000 ;
        RECT 127.330000 211.325000 127.680000 211.755000 ;
        RECT 127.330000 207.965000 127.680000 208.395000 ;
        RECT 1.980000 221.405000 6.180000 221.835000 ;
        RECT 1.980000 214.685000 6.180000 215.115000 ;
        RECT 1.980000 218.045000 6.180000 218.475000 ;
        RECT 1.980000 224.765000 6.180000 225.195000 ;
        RECT 1.980000 228.125000 6.180000 228.555000 ;
        RECT 1.980000 238.205000 6.180000 238.635000 ;
        RECT 1.980000 231.485000 6.180000 231.915000 ;
        RECT 1.980000 234.845000 6.180000 235.275000 ;
        RECT 1.980000 241.565000 6.180000 241.995000 ;
        RECT 1.980000 244.925000 6.180000 245.355000 ;
        RECT 1.980000 248.285000 6.180000 248.715000 ;
        RECT 47.330000 221.405000 47.680000 221.835000 ;
        RECT 47.330000 218.045000 47.680000 218.475000 ;
        RECT 47.330000 214.685000 47.680000 215.115000 ;
        RECT 47.330000 224.765000 47.680000 225.195000 ;
        RECT 47.330000 228.125000 47.680000 228.555000 ;
        RECT 47.330000 238.205000 47.680000 238.635000 ;
        RECT 47.330000 234.845000 47.680000 235.275000 ;
        RECT 47.330000 231.485000 47.680000 231.915000 ;
        RECT 47.330000 244.925000 47.680000 245.355000 ;
        RECT 47.330000 241.565000 47.680000 241.995000 ;
        RECT 47.330000 248.285000 47.680000 248.715000 ;
        RECT 1.980000 251.645000 6.180000 252.075000 ;
        RECT 1.980000 255.005000 6.180000 255.435000 ;
        RECT 1.980000 258.365000 6.180000 258.795000 ;
        RECT 47.330000 258.365000 47.680000 258.795000 ;
        RECT 47.330000 255.005000 47.680000 255.435000 ;
        RECT 47.330000 251.645000 47.680000 252.075000 ;
        RECT 87.330000 221.405000 87.680000 221.835000 ;
        RECT 87.330000 218.045000 87.680000 218.475000 ;
        RECT 87.330000 214.685000 87.680000 215.115000 ;
        RECT 87.330000 224.765000 87.680000 225.195000 ;
        RECT 87.330000 228.125000 87.680000 228.555000 ;
        RECT 87.330000 234.845000 87.680000 235.275000 ;
        RECT 87.330000 231.485000 87.680000 231.915000 ;
        RECT 87.330000 238.205000 87.680000 238.635000 ;
        RECT 87.330000 244.925000 87.680000 245.355000 ;
        RECT 87.330000 241.565000 87.680000 241.995000 ;
        RECT 87.330000 248.285000 87.680000 248.715000 ;
        RECT 127.330000 221.405000 127.680000 221.835000 ;
        RECT 127.330000 218.045000 127.680000 218.475000 ;
        RECT 127.330000 214.685000 127.680000 215.115000 ;
        RECT 127.330000 224.765000 127.680000 225.195000 ;
        RECT 127.330000 228.125000 127.680000 228.555000 ;
        RECT 127.330000 238.205000 127.680000 238.635000 ;
        RECT 127.330000 234.845000 127.680000 235.275000 ;
        RECT 127.330000 231.485000 127.680000 231.915000 ;
        RECT 127.330000 241.565000 127.680000 241.995000 ;
        RECT 127.330000 244.925000 127.680000 245.355000 ;
        RECT 127.330000 248.285000 127.680000 248.715000 ;
        RECT 87.330000 251.645000 87.680000 252.075000 ;
        RECT 87.330000 258.365000 87.680000 258.795000 ;
        RECT 87.330000 255.005000 87.680000 255.435000 ;
        RECT 127.330000 251.645000 127.680000 252.075000 ;
        RECT 127.330000 255.005000 127.680000 255.435000 ;
        RECT 127.330000 258.365000 127.680000 258.795000 ;
        RECT 167.330000 140.765000 167.680000 141.195000 ;
        RECT 167.330000 144.125000 167.680000 144.555000 ;
        RECT 167.330000 147.485000 167.680000 147.915000 ;
        RECT 167.330000 150.845000 167.680000 151.275000 ;
        RECT 167.330000 154.205000 167.680000 154.635000 ;
        RECT 167.330000 157.565000 167.680000 157.995000 ;
        RECT 167.330000 160.925000 167.680000 161.355000 ;
        RECT 167.330000 164.285000 167.680000 164.715000 ;
        RECT 167.330000 174.365000 167.680000 174.795000 ;
        RECT 167.330000 171.005000 167.680000 171.435000 ;
        RECT 167.330000 167.645000 167.680000 168.075000 ;
        RECT 207.330000 140.765000 207.680000 141.195000 ;
        RECT 207.330000 144.125000 207.680000 144.555000 ;
        RECT 207.330000 147.485000 207.680000 147.915000 ;
        RECT 207.330000 150.845000 207.680000 151.275000 ;
        RECT 207.330000 154.205000 207.680000 154.635000 ;
        RECT 207.330000 157.565000 207.680000 157.995000 ;
        RECT 207.330000 160.925000 207.680000 161.355000 ;
        RECT 207.330000 164.285000 207.680000 164.715000 ;
        RECT 207.330000 167.645000 207.680000 168.075000 ;
        RECT 207.330000 174.365000 207.680000 174.795000 ;
        RECT 207.330000 171.005000 207.680000 171.435000 ;
        RECT 167.330000 177.725000 167.680000 178.155000 ;
        RECT 167.330000 181.085000 167.680000 181.515000 ;
        RECT 167.330000 184.445000 167.680000 184.875000 ;
        RECT 167.330000 187.805000 167.680000 188.235000 ;
        RECT 167.330000 191.165000 167.680000 191.595000 ;
        RECT 167.330000 194.525000 167.680000 194.955000 ;
        RECT 167.330000 197.885000 167.680000 198.315000 ;
        RECT 167.330000 201.245000 167.680000 201.675000 ;
        RECT 167.330000 204.605000 167.680000 205.035000 ;
        RECT 167.330000 207.965000 167.680000 208.395000 ;
        RECT 167.330000 211.325000 167.680000 211.755000 ;
        RECT 207.330000 181.085000 207.680000 181.515000 ;
        RECT 207.330000 177.725000 207.680000 178.155000 ;
        RECT 207.330000 184.445000 207.680000 184.875000 ;
        RECT 207.330000 187.805000 207.680000 188.235000 ;
        RECT 207.330000 191.165000 207.680000 191.595000 ;
        RECT 207.330000 197.885000 207.680000 198.315000 ;
        RECT 207.330000 194.525000 207.680000 194.955000 ;
        RECT 207.330000 201.245000 207.680000 201.675000 ;
        RECT 207.330000 204.605000 207.680000 205.035000 ;
        RECT 207.330000 207.965000 207.680000 208.395000 ;
        RECT 207.330000 211.325000 207.680000 211.755000 ;
        RECT 247.330000 140.765000 247.680000 141.195000 ;
        RECT 247.330000 144.125000 247.680000 144.555000 ;
        RECT 247.330000 147.485000 247.680000 147.915000 ;
        RECT 247.330000 150.845000 247.680000 151.275000 ;
        RECT 247.330000 154.205000 247.680000 154.635000 ;
        RECT 247.330000 157.565000 247.680000 157.995000 ;
        RECT 247.330000 160.925000 247.680000 161.355000 ;
        RECT 247.330000 164.285000 247.680000 164.715000 ;
        RECT 247.330000 167.645000 247.680000 168.075000 ;
        RECT 247.330000 171.005000 247.680000 171.435000 ;
        RECT 247.330000 174.365000 247.680000 174.795000 ;
        RECT 293.840000 140.765000 298.040000 141.195000 ;
        RECT 293.840000 144.125000 298.040000 144.555000 ;
        RECT 293.840000 147.485000 298.040000 147.915000 ;
        RECT 293.840000 150.845000 298.040000 151.275000 ;
        RECT 293.840000 154.205000 298.040000 154.635000 ;
        RECT 293.840000 157.565000 298.040000 157.995000 ;
        RECT 293.840000 160.925000 298.040000 161.355000 ;
        RECT 293.840000 164.285000 298.040000 164.715000 ;
        RECT 293.840000 174.365000 298.040000 174.795000 ;
        RECT 293.840000 167.645000 298.040000 168.075000 ;
        RECT 293.840000 171.005000 298.040000 171.435000 ;
        RECT 247.330000 177.725000 247.680000 178.155000 ;
        RECT 247.330000 181.085000 247.680000 181.515000 ;
        RECT 247.330000 187.805000 247.680000 188.235000 ;
        RECT 247.330000 184.445000 247.680000 184.875000 ;
        RECT 247.330000 191.165000 247.680000 191.595000 ;
        RECT 247.330000 194.525000 247.680000 194.955000 ;
        RECT 247.330000 197.885000 247.680000 198.315000 ;
        RECT 247.330000 201.245000 247.680000 201.675000 ;
        RECT 247.330000 204.605000 247.680000 205.035000 ;
        RECT 247.330000 211.325000 247.680000 211.755000 ;
        RECT 247.330000 207.965000 247.680000 208.395000 ;
        RECT 293.840000 177.725000 298.040000 178.155000 ;
        RECT 293.840000 181.085000 298.040000 181.515000 ;
        RECT 293.840000 191.165000 298.040000 191.595000 ;
        RECT 293.840000 184.445000 298.040000 184.875000 ;
        RECT 293.840000 187.805000 298.040000 188.235000 ;
        RECT 293.840000 194.525000 298.040000 194.955000 ;
        RECT 293.840000 197.885000 298.040000 198.315000 ;
        RECT 293.840000 201.245000 298.040000 201.675000 ;
        RECT 293.840000 204.605000 298.040000 205.035000 ;
        RECT 293.840000 207.965000 298.040000 208.395000 ;
        RECT 293.840000 211.325000 298.040000 211.755000 ;
        RECT 167.330000 221.405000 167.680000 221.835000 ;
        RECT 167.330000 218.045000 167.680000 218.475000 ;
        RECT 167.330000 214.685000 167.680000 215.115000 ;
        RECT 167.330000 224.765000 167.680000 225.195000 ;
        RECT 167.330000 228.125000 167.680000 228.555000 ;
        RECT 167.330000 238.205000 167.680000 238.635000 ;
        RECT 167.330000 234.845000 167.680000 235.275000 ;
        RECT 167.330000 231.485000 167.680000 231.915000 ;
        RECT 167.330000 241.565000 167.680000 241.995000 ;
        RECT 167.330000 244.925000 167.680000 245.355000 ;
        RECT 167.330000 248.285000 167.680000 248.715000 ;
        RECT 207.330000 221.405000 207.680000 221.835000 ;
        RECT 207.330000 218.045000 207.680000 218.475000 ;
        RECT 207.330000 214.685000 207.680000 215.115000 ;
        RECT 207.330000 228.125000 207.680000 228.555000 ;
        RECT 207.330000 224.765000 207.680000 225.195000 ;
        RECT 207.330000 238.205000 207.680000 238.635000 ;
        RECT 207.330000 234.845000 207.680000 235.275000 ;
        RECT 207.330000 231.485000 207.680000 231.915000 ;
        RECT 207.330000 248.285000 207.680000 248.715000 ;
        RECT 207.330000 244.925000 207.680000 245.355000 ;
        RECT 207.330000 241.565000 207.680000 241.995000 ;
        RECT 167.330000 251.645000 167.680000 252.075000 ;
        RECT 167.330000 255.005000 167.680000 255.435000 ;
        RECT 167.330000 258.365000 167.680000 258.795000 ;
        RECT 207.330000 251.645000 207.680000 252.075000 ;
        RECT 207.330000 255.005000 207.680000 255.435000 ;
        RECT 207.330000 258.365000 207.680000 258.795000 ;
        RECT 247.330000 214.685000 247.680000 215.115000 ;
        RECT 247.330000 218.045000 247.680000 218.475000 ;
        RECT 247.330000 221.405000 247.680000 221.835000 ;
        RECT 247.330000 224.765000 247.680000 225.195000 ;
        RECT 247.330000 228.125000 247.680000 228.555000 ;
        RECT 247.330000 238.205000 247.680000 238.635000 ;
        RECT 247.330000 234.845000 247.680000 235.275000 ;
        RECT 247.330000 231.485000 247.680000 231.915000 ;
        RECT 247.330000 241.565000 247.680000 241.995000 ;
        RECT 247.330000 244.925000 247.680000 245.355000 ;
        RECT 247.330000 248.285000 247.680000 248.715000 ;
        RECT 293.840000 221.405000 298.040000 221.835000 ;
        RECT 293.840000 214.685000 298.040000 215.115000 ;
        RECT 293.840000 218.045000 298.040000 218.475000 ;
        RECT 293.840000 224.765000 298.040000 225.195000 ;
        RECT 293.840000 228.125000 298.040000 228.555000 ;
        RECT 293.840000 238.205000 298.040000 238.635000 ;
        RECT 293.840000 231.485000 298.040000 231.915000 ;
        RECT 293.840000 234.845000 298.040000 235.275000 ;
        RECT 293.840000 241.565000 298.040000 241.995000 ;
        RECT 293.840000 244.925000 298.040000 245.355000 ;
        RECT 293.840000 248.285000 298.040000 248.715000 ;
        RECT 247.330000 258.365000 247.680000 258.795000 ;
        RECT 247.330000 255.005000 247.680000 255.435000 ;
        RECT 247.330000 251.645000 247.680000 252.075000 ;
        RECT 293.840000 251.645000 298.040000 252.075000 ;
        RECT 293.840000 255.005000 298.040000 255.435000 ;
        RECT 293.840000 258.365000 298.040000 258.795000 ;
    END
# end of P/G power stripe data as pin

  END VSS
  PIN VDD
    DIRECTION INOUT ;
    USE POWER ;

# P/G power stripe data as pin
    PORT
      LAYER M3 ;
        RECT 8.780000 24.845000 12.980000 25.275000 ;
        RECT 44.980000 24.845000 45.330000 25.275000 ;
        RECT 8.780000 14.765000 12.980000 15.195000 ;
        RECT 8.780000 21.485000 12.980000 21.915000 ;
        RECT 8.780000 18.125000 12.980000 18.555000 ;
        RECT 44.980000 14.765000 45.330000 15.195000 ;
        RECT 44.980000 18.125000 45.330000 18.555000 ;
        RECT 44.980000 21.485000 45.330000 21.915000 ;
        RECT 8.780000 28.205000 12.980000 28.635000 ;
        RECT 8.780000 31.565000 12.980000 31.995000 ;
        RECT 8.780000 34.925000 12.980000 35.355000 ;
        RECT 8.780000 38.285000 12.980000 38.715000 ;
        RECT 8.780000 41.645000 12.980000 42.075000 ;
        RECT 8.780000 45.005000 12.980000 45.435000 ;
        RECT 8.780000 51.725000 12.980000 52.155000 ;
        RECT 8.780000 48.365000 12.980000 48.795000 ;
        RECT 8.780000 61.805000 12.980000 62.235000 ;
        RECT 8.780000 58.445000 12.980000 58.875000 ;
        RECT 8.780000 55.085000 12.980000 55.515000 ;
        RECT 44.980000 28.205000 45.330000 28.635000 ;
        RECT 44.980000 31.565000 45.330000 31.995000 ;
        RECT 44.980000 34.925000 45.330000 35.355000 ;
        RECT 44.980000 38.285000 45.330000 38.715000 ;
        RECT 44.980000 41.645000 45.330000 42.075000 ;
        RECT 44.980000 48.365000 45.330000 48.795000 ;
        RECT 44.980000 51.725000 45.330000 52.155000 ;
        RECT 44.980000 45.005000 45.330000 45.435000 ;
        RECT 44.980000 55.085000 45.330000 55.515000 ;
        RECT 44.980000 58.445000 45.330000 58.875000 ;
        RECT 44.980000 61.805000 45.330000 62.235000 ;
        RECT 124.980000 24.845000 125.330000 25.275000 ;
        RECT 84.980000 24.845000 85.330000 25.275000 ;
        RECT 84.980000 14.765000 85.330000 15.195000 ;
        RECT 84.980000 18.125000 85.330000 18.555000 ;
        RECT 84.980000 21.485000 85.330000 21.915000 ;
        RECT 124.980000 14.765000 125.330000 15.195000 ;
        RECT 124.980000 18.125000 125.330000 18.555000 ;
        RECT 124.980000 21.485000 125.330000 21.915000 ;
        RECT 84.980000 28.205000 85.330000 28.635000 ;
        RECT 84.980000 31.565000 85.330000 31.995000 ;
        RECT 84.980000 34.925000 85.330000 35.355000 ;
        RECT 84.980000 38.285000 85.330000 38.715000 ;
        RECT 84.980000 41.645000 85.330000 42.075000 ;
        RECT 84.980000 51.725000 85.330000 52.155000 ;
        RECT 84.980000 48.365000 85.330000 48.795000 ;
        RECT 84.980000 45.005000 85.330000 45.435000 ;
        RECT 84.980000 58.445000 85.330000 58.875000 ;
        RECT 84.980000 61.805000 85.330000 62.235000 ;
        RECT 84.980000 55.085000 85.330000 55.515000 ;
        RECT 124.980000 28.205000 125.330000 28.635000 ;
        RECT 124.980000 31.565000 125.330000 31.995000 ;
        RECT 124.980000 34.925000 125.330000 35.355000 ;
        RECT 124.980000 38.285000 125.330000 38.715000 ;
        RECT 124.980000 41.645000 125.330000 42.075000 ;
        RECT 124.980000 51.725000 125.330000 52.155000 ;
        RECT 124.980000 48.365000 125.330000 48.795000 ;
        RECT 124.980000 45.005000 125.330000 45.435000 ;
        RECT 124.980000 55.085000 125.330000 55.515000 ;
        RECT 124.980000 58.445000 125.330000 58.875000 ;
        RECT 124.980000 61.805000 125.330000 62.235000 ;
        RECT 8.780000 65.165000 12.980000 65.595000 ;
        RECT 8.780000 68.525000 12.980000 68.955000 ;
        RECT 8.780000 71.885000 12.980000 72.315000 ;
        RECT 8.780000 75.245000 12.980000 75.675000 ;
        RECT 8.780000 78.605000 12.980000 79.035000 ;
        RECT 8.780000 81.685000 12.980000 82.115000 ;
        RECT 8.780000 88.685000 12.980000 89.115000 ;
        RECT 8.780000 85.325000 12.980000 85.755000 ;
        RECT 8.780000 98.765000 12.980000 99.195000 ;
        RECT 8.780000 95.405000 12.980000 95.835000 ;
        RECT 8.780000 92.045000 12.980000 92.475000 ;
        RECT 44.980000 65.165000 45.330000 65.595000 ;
        RECT 44.980000 68.525000 45.330000 68.955000 ;
        RECT 44.980000 78.605000 45.330000 79.035000 ;
        RECT 44.980000 75.245000 45.330000 75.675000 ;
        RECT 44.980000 71.885000 45.330000 72.315000 ;
        RECT 44.980000 85.325000 45.330000 85.755000 ;
        RECT 44.980000 88.685000 45.330000 89.115000 ;
        RECT 44.980000 81.965000 45.330000 82.395000 ;
        RECT 44.980000 92.045000 45.330000 92.475000 ;
        RECT 44.980000 95.405000 45.330000 95.835000 ;
        RECT 44.980000 98.765000 45.330000 99.195000 ;
        RECT 8.780000 102.125000 12.980000 102.555000 ;
        RECT 8.780000 105.485000 12.980000 105.915000 ;
        RECT 8.780000 108.845000 12.980000 109.275000 ;
        RECT 8.780000 112.205000 12.980000 112.635000 ;
        RECT 8.780000 115.565000 12.980000 115.995000 ;
        RECT 8.780000 118.925000 12.980000 119.355000 ;
        RECT 8.780000 125.645000 12.980000 126.075000 ;
        RECT 8.780000 122.285000 12.980000 122.715000 ;
        RECT 8.780000 135.725000 12.980000 136.155000 ;
        RECT 8.780000 132.365000 12.980000 132.795000 ;
        RECT 8.780000 129.005000 12.980000 129.435000 ;
        RECT 44.980000 108.845000 45.330000 109.275000 ;
        RECT 44.980000 105.485000 45.330000 105.915000 ;
        RECT 44.980000 102.125000 45.330000 102.555000 ;
        RECT 44.980000 112.205000 45.330000 112.635000 ;
        RECT 44.980000 115.565000 45.330000 115.995000 ;
        RECT 44.980000 118.925000 45.330000 119.355000 ;
        RECT 44.980000 125.645000 45.330000 126.075000 ;
        RECT 44.980000 122.285000 45.330000 122.715000 ;
        RECT 44.980000 135.725000 45.330000 136.155000 ;
        RECT 44.980000 132.365000 45.330000 132.795000 ;
        RECT 44.980000 129.005000 45.330000 129.435000 ;
        RECT 84.980000 65.165000 85.330000 65.595000 ;
        RECT 84.980000 68.525000 85.330000 68.955000 ;
        RECT 84.980000 71.885000 85.330000 72.315000 ;
        RECT 84.980000 75.245000 85.330000 75.675000 ;
        RECT 84.980000 78.605000 85.330000 79.035000 ;
        RECT 84.980000 88.685000 85.330000 89.115000 ;
        RECT 84.980000 85.325000 85.330000 85.755000 ;
        RECT 84.980000 81.965000 85.330000 82.395000 ;
        RECT 84.980000 92.045000 85.330000 92.475000 ;
        RECT 84.980000 95.405000 85.330000 95.835000 ;
        RECT 84.980000 98.765000 85.330000 99.195000 ;
        RECT 124.980000 65.165000 125.330000 65.595000 ;
        RECT 124.980000 68.525000 125.330000 68.955000 ;
        RECT 124.980000 71.885000 125.330000 72.315000 ;
        RECT 124.980000 75.245000 125.330000 75.675000 ;
        RECT 124.980000 78.605000 125.330000 79.035000 ;
        RECT 124.980000 85.325000 125.330000 85.755000 ;
        RECT 124.980000 81.965000 125.330000 82.395000 ;
        RECT 124.980000 88.685000 125.330000 89.115000 ;
        RECT 124.980000 92.045000 125.330000 92.475000 ;
        RECT 124.980000 98.765000 125.330000 99.195000 ;
        RECT 124.980000 95.405000 125.330000 95.835000 ;
        RECT 84.980000 108.845000 85.330000 109.275000 ;
        RECT 84.980000 105.485000 85.330000 105.915000 ;
        RECT 84.980000 102.125000 85.330000 102.555000 ;
        RECT 84.980000 112.205000 85.330000 112.635000 ;
        RECT 84.980000 115.565000 85.330000 115.995000 ;
        RECT 84.980000 118.925000 85.330000 119.355000 ;
        RECT 84.980000 122.285000 85.330000 122.715000 ;
        RECT 84.980000 125.645000 85.330000 126.075000 ;
        RECT 84.980000 129.005000 85.330000 129.435000 ;
        RECT 84.980000 135.725000 85.330000 136.155000 ;
        RECT 84.980000 132.365000 85.330000 132.795000 ;
        RECT 124.980000 108.845000 125.330000 109.275000 ;
        RECT 124.980000 105.485000 125.330000 105.915000 ;
        RECT 124.980000 102.125000 125.330000 102.555000 ;
        RECT 124.980000 112.205000 125.330000 112.635000 ;
        RECT 124.980000 115.565000 125.330000 115.995000 ;
        RECT 124.980000 118.925000 125.330000 119.355000 ;
        RECT 124.980000 122.285000 125.330000 122.715000 ;
        RECT 124.980000 125.645000 125.330000 126.075000 ;
        RECT 124.980000 135.725000 125.330000 136.155000 ;
        RECT 124.980000 132.365000 125.330000 132.795000 ;
        RECT 124.980000 129.005000 125.330000 129.435000 ;
        RECT 204.980000 24.845000 205.330000 25.275000 ;
        RECT 164.980000 24.845000 165.330000 25.275000 ;
        RECT 164.980000 14.765000 165.330000 15.195000 ;
        RECT 164.980000 18.125000 165.330000 18.555000 ;
        RECT 164.980000 21.485000 165.330000 21.915000 ;
        RECT 204.980000 14.765000 205.330000 15.195000 ;
        RECT 204.980000 21.485000 205.330000 21.915000 ;
        RECT 204.980000 18.125000 205.330000 18.555000 ;
        RECT 164.980000 28.205000 165.330000 28.635000 ;
        RECT 164.980000 31.565000 165.330000 31.995000 ;
        RECT 164.980000 34.925000 165.330000 35.355000 ;
        RECT 164.980000 38.285000 165.330000 38.715000 ;
        RECT 164.980000 41.645000 165.330000 42.075000 ;
        RECT 164.980000 51.725000 165.330000 52.155000 ;
        RECT 164.980000 48.365000 165.330000 48.795000 ;
        RECT 164.980000 45.005000 165.330000 45.435000 ;
        RECT 164.980000 55.085000 165.330000 55.515000 ;
        RECT 164.980000 61.805000 165.330000 62.235000 ;
        RECT 164.980000 58.445000 165.330000 58.875000 ;
        RECT 204.980000 41.645000 205.330000 42.075000 ;
        RECT 204.980000 38.285000 205.330000 38.715000 ;
        RECT 204.980000 34.925000 205.330000 35.355000 ;
        RECT 204.980000 31.565000 205.330000 31.995000 ;
        RECT 204.980000 28.205000 205.330000 28.635000 ;
        RECT 204.980000 51.725000 205.330000 52.155000 ;
        RECT 204.980000 48.365000 205.330000 48.795000 ;
        RECT 204.980000 45.005000 205.330000 45.435000 ;
        RECT 204.980000 61.805000 205.330000 62.235000 ;
        RECT 204.980000 58.445000 205.330000 58.875000 ;
        RECT 204.980000 55.085000 205.330000 55.515000 ;
        RECT 287.040000 24.845000 291.240000 25.275000 ;
        RECT 244.980000 24.845000 245.330000 25.275000 ;
        RECT 244.980000 14.765000 245.330000 15.195000 ;
        RECT 244.980000 18.125000 245.330000 18.555000 ;
        RECT 244.980000 21.485000 245.330000 21.915000 ;
        RECT 287.040000 14.765000 291.240000 15.195000 ;
        RECT 287.040000 21.485000 291.240000 21.915000 ;
        RECT 287.040000 18.125000 291.240000 18.555000 ;
        RECT 244.980000 28.205000 245.330000 28.635000 ;
        RECT 244.980000 31.565000 245.330000 31.995000 ;
        RECT 244.980000 34.925000 245.330000 35.355000 ;
        RECT 244.980000 38.285000 245.330000 38.715000 ;
        RECT 244.980000 41.645000 245.330000 42.075000 ;
        RECT 244.980000 48.365000 245.330000 48.795000 ;
        RECT 244.980000 45.005000 245.330000 45.435000 ;
        RECT 244.980000 51.725000 245.330000 52.155000 ;
        RECT 244.980000 55.085000 245.330000 55.515000 ;
        RECT 244.980000 58.445000 245.330000 58.875000 ;
        RECT 244.980000 61.805000 245.330000 62.235000 ;
        RECT 287.040000 28.205000 291.240000 28.635000 ;
        RECT 287.040000 31.565000 291.240000 31.995000 ;
        RECT 287.040000 34.925000 291.240000 35.355000 ;
        RECT 287.040000 38.285000 291.240000 38.715000 ;
        RECT 287.040000 41.645000 291.240000 42.075000 ;
        RECT 287.040000 45.005000 291.240000 45.435000 ;
        RECT 287.040000 51.725000 291.240000 52.155000 ;
        RECT 287.040000 48.365000 291.240000 48.795000 ;
        RECT 287.040000 61.805000 291.240000 62.235000 ;
        RECT 287.040000 58.445000 291.240000 58.875000 ;
        RECT 287.040000 55.085000 291.240000 55.515000 ;
        RECT 164.980000 65.165000 165.330000 65.595000 ;
        RECT 164.980000 68.525000 165.330000 68.955000 ;
        RECT 164.980000 71.885000 165.330000 72.315000 ;
        RECT 164.980000 75.245000 165.330000 75.675000 ;
        RECT 164.980000 78.605000 165.330000 79.035000 ;
        RECT 164.980000 81.965000 165.330000 82.395000 ;
        RECT 164.980000 85.325000 165.330000 85.755000 ;
        RECT 164.980000 88.685000 165.330000 89.115000 ;
        RECT 164.980000 92.045000 165.330000 92.475000 ;
        RECT 164.980000 95.405000 165.330000 95.835000 ;
        RECT 164.980000 98.765000 165.330000 99.195000 ;
        RECT 204.980000 78.605000 205.330000 79.035000 ;
        RECT 204.980000 75.245000 205.330000 75.675000 ;
        RECT 204.980000 71.885000 205.330000 72.315000 ;
        RECT 204.980000 68.525000 205.330000 68.955000 ;
        RECT 204.980000 65.165000 205.330000 65.595000 ;
        RECT 204.980000 81.965000 205.330000 82.395000 ;
        RECT 204.980000 85.325000 205.330000 85.755000 ;
        RECT 204.980000 88.685000 205.330000 89.115000 ;
        RECT 204.980000 92.045000 205.330000 92.475000 ;
        RECT 204.980000 95.405000 205.330000 95.835000 ;
        RECT 204.980000 98.765000 205.330000 99.195000 ;
        RECT 164.980000 108.845000 165.330000 109.275000 ;
        RECT 164.980000 105.485000 165.330000 105.915000 ;
        RECT 164.980000 102.125000 165.330000 102.555000 ;
        RECT 164.980000 112.205000 165.330000 112.635000 ;
        RECT 164.980000 115.565000 165.330000 115.995000 ;
        RECT 164.980000 118.925000 165.330000 119.355000 ;
        RECT 164.980000 122.285000 165.330000 122.715000 ;
        RECT 164.980000 125.645000 165.330000 126.075000 ;
        RECT 164.980000 132.365000 165.330000 132.795000 ;
        RECT 164.980000 135.725000 165.330000 136.155000 ;
        RECT 164.980000 129.005000 165.330000 129.435000 ;
        RECT 204.980000 108.845000 205.330000 109.275000 ;
        RECT 204.980000 105.485000 205.330000 105.915000 ;
        RECT 204.980000 102.125000 205.330000 102.555000 ;
        RECT 204.980000 112.205000 205.330000 112.635000 ;
        RECT 204.980000 115.565000 205.330000 115.995000 ;
        RECT 204.980000 118.925000 205.330000 119.355000 ;
        RECT 204.980000 122.285000 205.330000 122.715000 ;
        RECT 204.980000 125.645000 205.330000 126.075000 ;
        RECT 204.980000 129.005000 205.330000 129.435000 ;
        RECT 204.980000 132.365000 205.330000 132.795000 ;
        RECT 204.980000 135.725000 205.330000 136.155000 ;
        RECT 244.980000 65.165000 245.330000 65.595000 ;
        RECT 244.980000 68.525000 245.330000 68.955000 ;
        RECT 244.980000 71.885000 245.330000 72.315000 ;
        RECT 244.980000 75.245000 245.330000 75.675000 ;
        RECT 244.980000 78.605000 245.330000 79.035000 ;
        RECT 244.980000 81.965000 245.330000 82.395000 ;
        RECT 244.980000 85.325000 245.330000 85.755000 ;
        RECT 244.980000 88.685000 245.330000 89.115000 ;
        RECT 244.980000 92.045000 245.330000 92.475000 ;
        RECT 244.980000 95.405000 245.330000 95.835000 ;
        RECT 244.980000 98.765000 245.330000 99.195000 ;
        RECT 287.040000 65.165000 291.240000 65.595000 ;
        RECT 287.040000 68.525000 291.240000 68.955000 ;
        RECT 287.040000 71.885000 291.240000 72.315000 ;
        RECT 287.040000 75.245000 291.240000 75.675000 ;
        RECT 287.040000 78.605000 291.240000 79.035000 ;
        RECT 287.040000 81.685000 291.240000 82.115000 ;
        RECT 287.040000 88.685000 291.240000 89.115000 ;
        RECT 287.040000 85.325000 291.240000 85.755000 ;
        RECT 287.040000 98.765000 291.240000 99.195000 ;
        RECT 287.040000 95.405000 291.240000 95.835000 ;
        RECT 287.040000 92.045000 291.240000 92.475000 ;
        RECT 244.980000 102.125000 245.330000 102.555000 ;
        RECT 244.980000 105.485000 245.330000 105.915000 ;
        RECT 244.980000 108.845000 245.330000 109.275000 ;
        RECT 244.980000 112.205000 245.330000 112.635000 ;
        RECT 244.980000 115.565000 245.330000 115.995000 ;
        RECT 244.980000 118.925000 245.330000 119.355000 ;
        RECT 244.980000 125.645000 245.330000 126.075000 ;
        RECT 244.980000 122.285000 245.330000 122.715000 ;
        RECT 244.980000 132.365000 245.330000 132.795000 ;
        RECT 244.980000 129.005000 245.330000 129.435000 ;
        RECT 244.980000 135.725000 245.330000 136.155000 ;
        RECT 287.040000 102.125000 291.240000 102.555000 ;
        RECT 287.040000 105.485000 291.240000 105.915000 ;
        RECT 287.040000 108.845000 291.240000 109.275000 ;
        RECT 287.040000 112.205000 291.240000 112.635000 ;
        RECT 287.040000 115.565000 291.240000 115.995000 ;
        RECT 287.040000 118.925000 291.240000 119.355000 ;
        RECT 287.040000 125.645000 291.240000 126.075000 ;
        RECT 287.040000 122.285000 291.240000 122.715000 ;
        RECT 287.040000 135.725000 291.240000 136.155000 ;
        RECT 287.040000 132.365000 291.240000 132.795000 ;
        RECT 287.040000 129.005000 291.240000 129.435000 ;
        RECT 8.780000 155.885000 12.980000 156.315000 ;
        RECT 8.780000 139.085000 12.980000 139.515000 ;
        RECT 8.780000 142.445000 12.980000 142.875000 ;
        RECT 8.780000 145.805000 12.980000 146.235000 ;
        RECT 8.780000 152.945000 12.980000 153.375000 ;
        RECT 8.780000 149.165000 12.980000 149.595000 ;
        RECT 8.780000 162.605000 12.980000 163.035000 ;
        RECT 8.780000 159.245000 12.980000 159.675000 ;
        RECT 8.780000 172.685000 12.980000 173.115000 ;
        RECT 8.780000 169.325000 12.980000 169.755000 ;
        RECT 8.780000 165.965000 12.980000 166.395000 ;
        RECT 44.980000 155.885000 45.330000 156.315000 ;
        RECT 44.980000 139.085000 45.330000 139.515000 ;
        RECT 44.980000 142.445000 45.330000 142.875000 ;
        RECT 44.980000 145.805000 45.330000 146.235000 ;
        RECT 44.980000 149.165000 45.330000 149.595000 ;
        RECT 44.980000 152.525000 45.330000 152.955000 ;
        RECT 44.980000 159.245000 45.330000 159.675000 ;
        RECT 44.980000 162.605000 45.330000 163.035000 ;
        RECT 44.980000 165.965000 45.330000 166.395000 ;
        RECT 44.980000 169.325000 45.330000 169.755000 ;
        RECT 44.980000 172.685000 45.330000 173.115000 ;
        RECT 8.780000 176.045000 12.980000 176.475000 ;
        RECT 8.780000 179.405000 12.980000 179.835000 ;
        RECT 8.780000 182.765000 12.980000 183.195000 ;
        RECT 8.780000 186.125000 12.980000 186.555000 ;
        RECT 8.780000 189.485000 12.980000 189.915000 ;
        RECT 8.780000 192.845000 12.980000 193.275000 ;
        RECT 8.780000 202.925000 12.980000 203.355000 ;
        RECT 8.780000 199.565000 12.980000 199.995000 ;
        RECT 8.780000 196.205000 12.980000 196.635000 ;
        RECT 8.780000 209.645000 12.980000 210.075000 ;
        RECT 8.780000 206.285000 12.980000 206.715000 ;
        RECT 44.980000 176.045000 45.330000 176.475000 ;
        RECT 44.980000 179.405000 45.330000 179.835000 ;
        RECT 44.980000 182.765000 45.330000 183.195000 ;
        RECT 44.980000 192.845000 45.330000 193.275000 ;
        RECT 44.980000 189.485000 45.330000 189.915000 ;
        RECT 44.980000 186.125000 45.330000 186.555000 ;
        RECT 44.980000 202.925000 45.330000 203.355000 ;
        RECT 44.980000 196.205000 45.330000 196.635000 ;
        RECT 44.980000 199.565000 45.330000 199.995000 ;
        RECT 44.980000 209.645000 45.330000 210.075000 ;
        RECT 44.980000 206.285000 45.330000 206.715000 ;
        RECT 84.980000 155.885000 85.330000 156.315000 ;
        RECT 84.980000 139.085000 85.330000 139.515000 ;
        RECT 84.980000 142.445000 85.330000 142.875000 ;
        RECT 84.980000 145.805000 85.330000 146.235000 ;
        RECT 84.980000 149.165000 85.330000 149.595000 ;
        RECT 84.980000 152.525000 85.330000 152.955000 ;
        RECT 84.980000 159.245000 85.330000 159.675000 ;
        RECT 84.980000 162.605000 85.330000 163.035000 ;
        RECT 84.980000 172.685000 85.330000 173.115000 ;
        RECT 84.980000 169.325000 85.330000 169.755000 ;
        RECT 84.980000 165.965000 85.330000 166.395000 ;
        RECT 124.980000 155.885000 125.330000 156.315000 ;
        RECT 124.980000 139.085000 125.330000 139.515000 ;
        RECT 124.980000 142.445000 125.330000 142.875000 ;
        RECT 124.980000 145.805000 125.330000 146.235000 ;
        RECT 124.980000 149.165000 125.330000 149.595000 ;
        RECT 124.980000 152.525000 125.330000 152.955000 ;
        RECT 124.980000 162.605000 125.330000 163.035000 ;
        RECT 124.980000 159.245000 125.330000 159.675000 ;
        RECT 124.980000 165.965000 125.330000 166.395000 ;
        RECT 124.980000 172.685000 125.330000 173.115000 ;
        RECT 124.980000 169.325000 125.330000 169.755000 ;
        RECT 84.980000 182.765000 85.330000 183.195000 ;
        RECT 84.980000 179.405000 85.330000 179.835000 ;
        RECT 84.980000 176.045000 85.330000 176.475000 ;
        RECT 84.980000 186.125000 85.330000 186.555000 ;
        RECT 84.980000 189.485000 85.330000 189.915000 ;
        RECT 84.980000 192.845000 85.330000 193.275000 ;
        RECT 84.980000 202.925000 85.330000 203.355000 ;
        RECT 84.980000 196.205000 85.330000 196.635000 ;
        RECT 84.980000 199.565000 85.330000 199.995000 ;
        RECT 84.980000 206.285000 85.330000 206.715000 ;
        RECT 84.980000 209.645000 85.330000 210.075000 ;
        RECT 124.980000 176.045000 125.330000 176.475000 ;
        RECT 124.980000 179.405000 125.330000 179.835000 ;
        RECT 124.980000 182.765000 125.330000 183.195000 ;
        RECT 124.980000 186.125000 125.330000 186.555000 ;
        RECT 124.980000 189.485000 125.330000 189.915000 ;
        RECT 124.980000 192.845000 125.330000 193.275000 ;
        RECT 124.980000 202.925000 125.330000 203.355000 ;
        RECT 124.980000 199.565000 125.330000 199.995000 ;
        RECT 124.980000 196.205000 125.330000 196.635000 ;
        RECT 124.980000 206.285000 125.330000 206.715000 ;
        RECT 124.980000 209.645000 125.330000 210.075000 ;
        RECT 8.780000 249.965000 12.980000 250.395000 ;
        RECT 44.980000 249.965000 45.330000 250.395000 ;
        RECT 8.780000 213.005000 12.980000 213.435000 ;
        RECT 8.780000 216.365000 12.980000 216.795000 ;
        RECT 8.780000 219.725000 12.980000 220.155000 ;
        RECT 8.780000 223.085000 12.980000 223.515000 ;
        RECT 8.780000 226.445000 12.980000 226.875000 ;
        RECT 8.780000 229.805000 12.980000 230.235000 ;
        RECT 8.780000 239.885000 12.980000 240.315000 ;
        RECT 8.780000 236.525000 12.980000 236.955000 ;
        RECT 8.780000 233.165000 12.980000 233.595000 ;
        RECT 8.780000 246.605000 12.980000 247.035000 ;
        RECT 8.780000 243.245000 12.980000 243.675000 ;
        RECT 44.980000 219.725000 45.330000 220.155000 ;
        RECT 44.980000 216.365000 45.330000 216.795000 ;
        RECT 44.980000 213.005000 45.330000 213.435000 ;
        RECT 44.980000 223.085000 45.330000 223.515000 ;
        RECT 44.980000 226.445000 45.330000 226.875000 ;
        RECT 44.980000 229.805000 45.330000 230.235000 ;
        RECT 44.980000 239.885000 45.330000 240.315000 ;
        RECT 44.980000 236.525000 45.330000 236.955000 ;
        RECT 44.980000 233.165000 45.330000 233.595000 ;
        RECT 44.980000 246.605000 45.330000 247.035000 ;
        RECT 44.980000 243.245000 45.330000 243.675000 ;
        RECT 8.780000 256.685000 12.980000 257.115000 ;
        RECT 8.780000 253.325000 12.980000 253.755000 ;
        RECT 44.980000 253.325000 45.330000 253.755000 ;
        RECT 44.980000 256.685000 45.330000 257.115000 ;
        RECT 124.980000 249.965000 125.330000 250.395000 ;
        RECT 84.980000 249.965000 85.330000 250.395000 ;
        RECT 84.980000 219.725000 85.330000 220.155000 ;
        RECT 84.980000 216.365000 85.330000 216.795000 ;
        RECT 84.980000 213.005000 85.330000 213.435000 ;
        RECT 84.980000 226.445000 85.330000 226.875000 ;
        RECT 84.980000 223.085000 85.330000 223.515000 ;
        RECT 84.980000 229.805000 85.330000 230.235000 ;
        RECT 84.980000 233.165000 85.330000 233.595000 ;
        RECT 84.980000 236.525000 85.330000 236.955000 ;
        RECT 84.980000 239.885000 85.330000 240.315000 ;
        RECT 84.980000 243.245000 85.330000 243.675000 ;
        RECT 84.980000 246.605000 85.330000 247.035000 ;
        RECT 124.980000 219.725000 125.330000 220.155000 ;
        RECT 124.980000 216.365000 125.330000 216.795000 ;
        RECT 124.980000 213.005000 125.330000 213.435000 ;
        RECT 124.980000 223.085000 125.330000 223.515000 ;
        RECT 124.980000 226.445000 125.330000 226.875000 ;
        RECT 124.980000 229.805000 125.330000 230.235000 ;
        RECT 124.980000 233.165000 125.330000 233.595000 ;
        RECT 124.980000 236.525000 125.330000 236.955000 ;
        RECT 124.980000 239.885000 125.330000 240.315000 ;
        RECT 124.980000 243.245000 125.330000 243.675000 ;
        RECT 124.980000 246.605000 125.330000 247.035000 ;
        RECT 84.980000 253.325000 85.330000 253.755000 ;
        RECT 84.980000 256.685000 85.330000 257.115000 ;
        RECT 124.980000 253.325000 125.330000 253.755000 ;
        RECT 124.980000 256.685000 125.330000 257.115000 ;
        RECT 164.980000 155.885000 165.330000 156.315000 ;
        RECT 164.980000 139.085000 165.330000 139.515000 ;
        RECT 164.980000 142.445000 165.330000 142.875000 ;
        RECT 164.980000 145.805000 165.330000 146.235000 ;
        RECT 164.980000 149.165000 165.330000 149.595000 ;
        RECT 164.980000 152.525000 165.330000 152.955000 ;
        RECT 164.980000 162.605000 165.330000 163.035000 ;
        RECT 164.980000 159.245000 165.330000 159.675000 ;
        RECT 164.980000 172.685000 165.330000 173.115000 ;
        RECT 164.980000 169.325000 165.330000 169.755000 ;
        RECT 164.980000 165.965000 165.330000 166.395000 ;
        RECT 204.980000 155.885000 205.330000 156.315000 ;
        RECT 204.980000 145.805000 205.330000 146.235000 ;
        RECT 204.980000 142.445000 205.330000 142.875000 ;
        RECT 204.980000 139.085000 205.330000 139.515000 ;
        RECT 204.980000 149.165000 205.330000 149.595000 ;
        RECT 204.980000 152.525000 205.330000 152.955000 ;
        RECT 204.980000 162.605000 205.330000 163.035000 ;
        RECT 204.980000 159.245000 205.330000 159.675000 ;
        RECT 204.980000 169.325000 205.330000 169.755000 ;
        RECT 204.980000 172.685000 205.330000 173.115000 ;
        RECT 204.980000 165.965000 205.330000 166.395000 ;
        RECT 164.980000 176.045000 165.330000 176.475000 ;
        RECT 164.980000 179.405000 165.330000 179.835000 ;
        RECT 164.980000 182.765000 165.330000 183.195000 ;
        RECT 164.980000 186.125000 165.330000 186.555000 ;
        RECT 164.980000 189.485000 165.330000 189.915000 ;
        RECT 164.980000 192.845000 165.330000 193.275000 ;
        RECT 164.980000 202.925000 165.330000 203.355000 ;
        RECT 164.980000 199.565000 165.330000 199.995000 ;
        RECT 164.980000 196.205000 165.330000 196.635000 ;
        RECT 164.980000 209.645000 165.330000 210.075000 ;
        RECT 164.980000 206.285000 165.330000 206.715000 ;
        RECT 204.980000 176.045000 205.330000 176.475000 ;
        RECT 204.980000 179.405000 205.330000 179.835000 ;
        RECT 204.980000 182.765000 205.330000 183.195000 ;
        RECT 204.980000 186.125000 205.330000 186.555000 ;
        RECT 204.980000 189.485000 205.330000 189.915000 ;
        RECT 204.980000 192.845000 205.330000 193.275000 ;
        RECT 204.980000 202.925000 205.330000 203.355000 ;
        RECT 204.980000 199.565000 205.330000 199.995000 ;
        RECT 204.980000 196.205000 205.330000 196.635000 ;
        RECT 204.980000 206.285000 205.330000 206.715000 ;
        RECT 204.980000 209.645000 205.330000 210.075000 ;
        RECT 244.980000 155.885000 245.330000 156.315000 ;
        RECT 244.980000 139.085000 245.330000 139.515000 ;
        RECT 244.980000 142.445000 245.330000 142.875000 ;
        RECT 244.980000 145.805000 245.330000 146.235000 ;
        RECT 244.980000 149.165000 245.330000 149.595000 ;
        RECT 244.980000 152.525000 245.330000 152.955000 ;
        RECT 244.980000 159.245000 245.330000 159.675000 ;
        RECT 244.980000 162.605000 245.330000 163.035000 ;
        RECT 244.980000 165.965000 245.330000 166.395000 ;
        RECT 244.980000 169.325000 245.330000 169.755000 ;
        RECT 244.980000 172.685000 245.330000 173.115000 ;
        RECT 287.040000 155.885000 291.240000 156.315000 ;
        RECT 287.040000 139.085000 291.240000 139.515000 ;
        RECT 287.040000 142.445000 291.240000 142.875000 ;
        RECT 287.040000 145.805000 291.240000 146.235000 ;
        RECT 287.040000 152.945000 291.240000 153.375000 ;
        RECT 287.040000 149.165000 291.240000 149.595000 ;
        RECT 287.040000 162.605000 291.240000 163.035000 ;
        RECT 287.040000 159.245000 291.240000 159.675000 ;
        RECT 287.040000 172.685000 291.240000 173.115000 ;
        RECT 287.040000 169.325000 291.240000 169.755000 ;
        RECT 287.040000 165.965000 291.240000 166.395000 ;
        RECT 244.980000 179.405000 245.330000 179.835000 ;
        RECT 244.980000 176.045000 245.330000 176.475000 ;
        RECT 244.980000 182.765000 245.330000 183.195000 ;
        RECT 244.980000 186.125000 245.330000 186.555000 ;
        RECT 244.980000 192.845000 245.330000 193.275000 ;
        RECT 244.980000 189.485000 245.330000 189.915000 ;
        RECT 244.980000 202.925000 245.330000 203.355000 ;
        RECT 244.980000 196.205000 245.330000 196.635000 ;
        RECT 244.980000 199.565000 245.330000 199.995000 ;
        RECT 244.980000 206.285000 245.330000 206.715000 ;
        RECT 244.980000 209.645000 245.330000 210.075000 ;
        RECT 287.040000 176.045000 291.240000 176.475000 ;
        RECT 287.040000 179.405000 291.240000 179.835000 ;
        RECT 287.040000 182.765000 291.240000 183.195000 ;
        RECT 287.040000 186.125000 291.240000 186.555000 ;
        RECT 287.040000 189.485000 291.240000 189.915000 ;
        RECT 287.040000 192.845000 291.240000 193.275000 ;
        RECT 287.040000 202.925000 291.240000 203.355000 ;
        RECT 287.040000 199.565000 291.240000 199.995000 ;
        RECT 287.040000 196.205000 291.240000 196.635000 ;
        RECT 287.040000 209.645000 291.240000 210.075000 ;
        RECT 287.040000 206.285000 291.240000 206.715000 ;
        RECT 204.980000 249.965000 205.330000 250.395000 ;
        RECT 164.980000 249.965000 165.330000 250.395000 ;
        RECT 164.980000 219.725000 165.330000 220.155000 ;
        RECT 164.980000 216.365000 165.330000 216.795000 ;
        RECT 164.980000 213.005000 165.330000 213.435000 ;
        RECT 164.980000 223.085000 165.330000 223.515000 ;
        RECT 164.980000 226.445000 165.330000 226.875000 ;
        RECT 164.980000 229.805000 165.330000 230.235000 ;
        RECT 164.980000 233.165000 165.330000 233.595000 ;
        RECT 164.980000 236.525000 165.330000 236.955000 ;
        RECT 164.980000 239.885000 165.330000 240.315000 ;
        RECT 164.980000 243.245000 165.330000 243.675000 ;
        RECT 164.980000 246.605000 165.330000 247.035000 ;
        RECT 204.980000 213.005000 205.330000 213.435000 ;
        RECT 204.980000 216.365000 205.330000 216.795000 ;
        RECT 204.980000 219.725000 205.330000 220.155000 ;
        RECT 204.980000 223.085000 205.330000 223.515000 ;
        RECT 204.980000 226.445000 205.330000 226.875000 ;
        RECT 204.980000 229.805000 205.330000 230.235000 ;
        RECT 204.980000 233.165000 205.330000 233.595000 ;
        RECT 204.980000 236.525000 205.330000 236.955000 ;
        RECT 204.980000 239.885000 205.330000 240.315000 ;
        RECT 204.980000 246.605000 205.330000 247.035000 ;
        RECT 204.980000 243.245000 205.330000 243.675000 ;
        RECT 164.980000 253.325000 165.330000 253.755000 ;
        RECT 164.980000 256.685000 165.330000 257.115000 ;
        RECT 204.980000 253.325000 205.330000 253.755000 ;
        RECT 204.980000 256.685000 205.330000 257.115000 ;
        RECT 287.040000 249.965000 291.240000 250.395000 ;
        RECT 244.980000 249.965000 245.330000 250.395000 ;
        RECT 244.980000 213.005000 245.330000 213.435000 ;
        RECT 244.980000 216.365000 245.330000 216.795000 ;
        RECT 244.980000 219.725000 245.330000 220.155000 ;
        RECT 244.980000 223.085000 245.330000 223.515000 ;
        RECT 244.980000 226.445000 245.330000 226.875000 ;
        RECT 244.980000 229.805000 245.330000 230.235000 ;
        RECT 244.980000 239.885000 245.330000 240.315000 ;
        RECT 244.980000 236.525000 245.330000 236.955000 ;
        RECT 244.980000 233.165000 245.330000 233.595000 ;
        RECT 244.980000 243.245000 245.330000 243.675000 ;
        RECT 244.980000 246.605000 245.330000 247.035000 ;
        RECT 287.040000 213.005000 291.240000 213.435000 ;
        RECT 287.040000 216.365000 291.240000 216.795000 ;
        RECT 287.040000 219.725000 291.240000 220.155000 ;
        RECT 287.040000 223.085000 291.240000 223.515000 ;
        RECT 287.040000 226.445000 291.240000 226.875000 ;
        RECT 287.040000 229.805000 291.240000 230.235000 ;
        RECT 287.040000 239.885000 291.240000 240.315000 ;
        RECT 287.040000 236.525000 291.240000 236.955000 ;
        RECT 287.040000 233.165000 291.240000 233.595000 ;
        RECT 287.040000 246.605000 291.240000 247.035000 ;
        RECT 287.040000 243.245000 291.240000 243.675000 ;
        RECT 244.980000 253.325000 245.330000 253.755000 ;
        RECT 244.980000 256.685000 245.330000 257.115000 ;
        RECT 287.040000 256.685000 291.240000 257.115000 ;
        RECT 287.040000 253.325000 291.240000 253.755000 ;
    END
# end of P/G power stripe data as pin

  END VDD
  OBS
    LAYER M1 ;
      RECT 0.000000 0.000000 300.020000 274.960000 ;
    LAYER M2 ;
      RECT 0.000000 0.000000 300.020000 274.960000 ;
    LAYER M3 ;
      RECT 0.000000 0.000000 300.020000 274.960000 ;
  END
END ibex_core

END LIBRARY
